VERSION 5.8 ;
BUSBITCHARS "[]" ;
DIVIDERCHAR "/" ;
UNITS
    DATABASE MICRONS 1000 ;
END UNITS

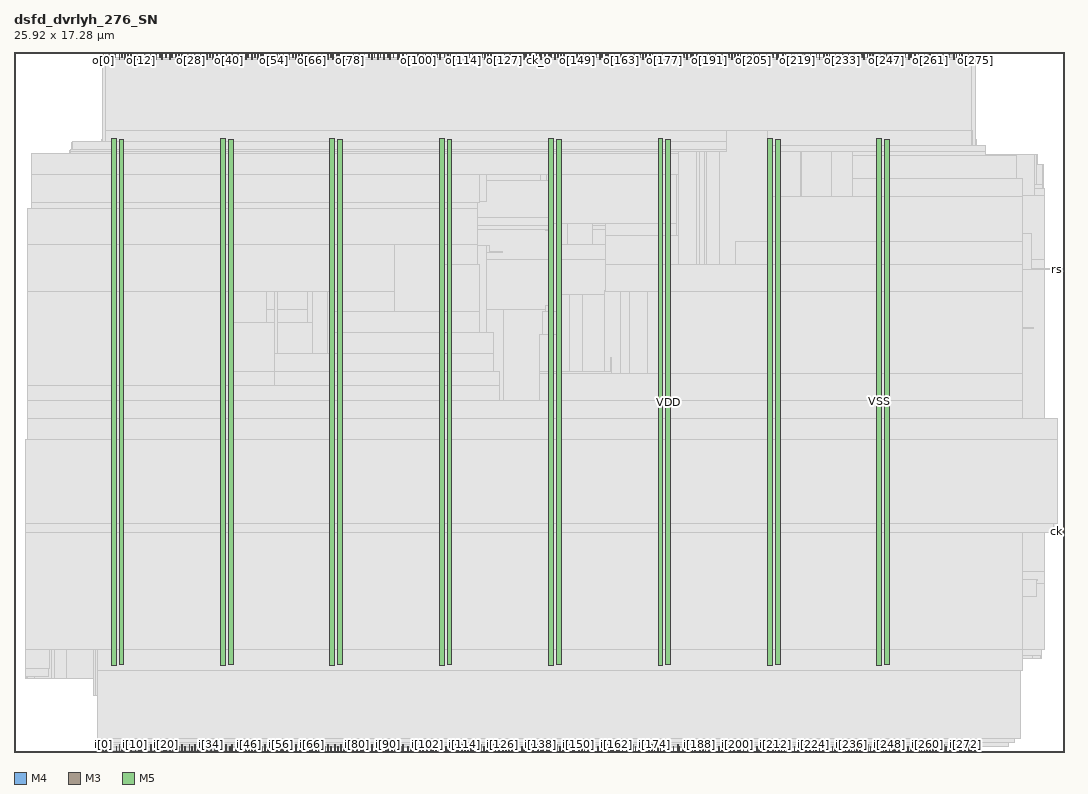
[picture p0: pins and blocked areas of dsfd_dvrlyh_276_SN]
MACRO dsfd_dvrlyh_276_SN
  FOREIGN dsfd_dvrlyh_276_SN 0 0 ;
  CLASS BLOCK ;
  SIZE 25.92 BY 17.28 ;
  PIN ck
    DIRECTION INPUT ;
    USE SIGNAL ;
    PORT
      LAYER M4 ;
        RECT  25.728 5.424 25.92 5.448 ;
    END
  END ck
  PIN ck_o
    DIRECTION OUTPUT ;
    USE SIGNAL ;
    PORT
      LAYER M3 ;
        RECT  12.96 17.136 12.978 17.28 ;
    END
  END ck_o
  PIN i[0]
    DIRECTION INPUT ;
    USE SIGNAL ;
    PORT
      LAYER M3 ;
        RECT  2.196 0 2.214 0.144 ;
    END
  END i[0]
  PIN i[100]
    DIRECTION INPUT ;
    USE SIGNAL ;
    PORT
      LAYER M3 ;
        RECT  10.008 0 10.026 0.144 ;
    END
  END i[100]
  PIN i[101]
    DIRECTION INPUT ;
    USE SIGNAL ;
    PORT
      LAYER M5 ;
        RECT  10.08 0 10.104 0.192 ;
    END
  END i[101]
  PIN i[102]
    DIRECTION INPUT ;
    USE SIGNAL ;
    PORT
      LAYER M3 ;
        RECT  10.188 0 10.206 0.144 ;
    END
  END i[102]
  PIN i[103]
    DIRECTION INPUT ;
    USE SIGNAL ;
    PORT
      LAYER M5 ;
        RECT  10.272 0 10.296 0.192 ;
    END
  END i[103]
  PIN i[104]
    DIRECTION INPUT ;
    USE SIGNAL ;
    PORT
      LAYER M3 ;
        RECT  10.332 0 10.35 0.144 ;
    END
  END i[104]
  PIN i[105]
    DIRECTION INPUT ;
    USE SIGNAL ;
    PORT
      LAYER M5 ;
        RECT  10.416 0 10.44 0.192 ;
    END
  END i[105]
  PIN i[106]
    DIRECTION INPUT ;
    USE SIGNAL ;
    PORT
      LAYER M3 ;
        RECT  10.476 0 10.494 0.144 ;
    END
  END i[106]
  PIN i[107]
    DIRECTION INPUT ;
    USE SIGNAL ;
    PORT
      LAYER M5 ;
        RECT  10.56 0 10.584 0.192 ;
    END
  END i[107]
  PIN i[108]
    DIRECTION INPUT ;
    USE SIGNAL ;
    PORT
      LAYER M3 ;
        RECT  10.656 0 10.674 0.144 ;
    END
  END i[108]
  PIN i[109]
    DIRECTION INPUT ;
    USE SIGNAL ;
    PORT
      LAYER M5 ;
        RECT  10.704 0 10.728 0.192 ;
    END
  END i[109]
  PIN i[10]
    DIRECTION INPUT ;
    USE SIGNAL ;
    PORT
      LAYER M3 ;
        RECT  2.988 0 3.006 0.144 ;
    END
  END i[10]
  PIN i[110]
    DIRECTION INPUT ;
    USE SIGNAL ;
    PORT
      LAYER M3 ;
        RECT  10.8 0 10.818 0.144 ;
    END
  END i[110]
  PIN i[111]
    DIRECTION INPUT ;
    USE SIGNAL ;
    PORT
      LAYER M5 ;
        RECT  10.896 0 10.92 0.192 ;
    END
  END i[111]
  PIN i[112]
    DIRECTION INPUT ;
    USE SIGNAL ;
    PORT
      LAYER M3 ;
        RECT  10.944 0 10.962 0.144 ;
    END
  END i[112]
  PIN i[113]
    DIRECTION INPUT ;
    USE SIGNAL ;
    PORT
      LAYER M5 ;
        RECT  11.04 0 11.064 0.192 ;
    END
  END i[113]
  PIN i[114]
    DIRECTION INPUT ;
    USE SIGNAL ;
    PORT
      LAYER M3 ;
        RECT  11.124 0 11.142 0.144 ;
    END
  END i[114]
  PIN i[115]
    DIRECTION INPUT ;
    USE SIGNAL ;
    PORT
      LAYER M5 ;
        RECT  11.184 0 11.208 0.192 ;
    END
  END i[115]
  PIN i[116]
    DIRECTION INPUT ;
    USE SIGNAL ;
    PORT
      LAYER M3 ;
        RECT  11.268 0 11.286 0.144 ;
    END
  END i[116]
  PIN i[117]
    DIRECTION INPUT ;
    USE SIGNAL ;
    PORT
      LAYER M5 ;
        RECT  11.328 0 11.352 0.192 ;
    END
  END i[117]
  PIN i[118]
    DIRECTION INPUT ;
    USE SIGNAL ;
    PORT
      LAYER M3 ;
        RECT  11.412 0 11.43 0.144 ;
    END
  END i[118]
  PIN i[119]
    DIRECTION INPUT ;
    USE SIGNAL ;
    PORT
      LAYER M5 ;
        RECT  11.52 0 11.544 0.192 ;
    END
  END i[119]
  PIN i[11]
    DIRECTION INPUT ;
    USE SIGNAL ;
    PORT
      LAYER M5 ;
        RECT  3.072 0 3.096 0.192 ;
    END
  END i[11]
  PIN i[120]
    DIRECTION INPUT ;
    USE SIGNAL ;
    PORT
      LAYER M3 ;
        RECT  11.592 0 11.61 0.144 ;
    END
  END i[120]
  PIN i[121]
    DIRECTION INPUT ;
    USE SIGNAL ;
    PORT
      LAYER M5 ;
        RECT  11.664 0 11.688 0.192 ;
    END
  END i[121]
  PIN i[122]
    DIRECTION INPUT ;
    USE SIGNAL ;
    PORT
      LAYER M3 ;
        RECT  11.736 0 11.754 0.144 ;
    END
  END i[122]
  PIN i[123]
    DIRECTION INPUT ;
    USE SIGNAL ;
    PORT
      LAYER M5 ;
        RECT  11.808 0 11.832 0.192 ;
    END
  END i[123]
  PIN i[124]
    DIRECTION INPUT ;
    USE SIGNAL ;
    PORT
      LAYER M3 ;
        RECT  11.88 0 11.898 0.144 ;
    END
  END i[124]
  PIN i[125]
    DIRECTION INPUT ;
    USE SIGNAL ;
    PORT
      LAYER M5 ;
        RECT  11.952 0 11.976 0.192 ;
    END
  END i[125]
  PIN i[126]
    DIRECTION INPUT ;
    USE SIGNAL ;
    PORT
      LAYER M3 ;
        RECT  12.06 0 12.078 0.144 ;
    END
  END i[126]
  PIN i[127]
    DIRECTION INPUT ;
    USE SIGNAL ;
    PORT
      LAYER M5 ;
        RECT  12.144 0 12.168 0.192 ;
    END
  END i[127]
  PIN i[128]
    DIRECTION INPUT ;
    USE SIGNAL ;
    PORT
      LAYER M3 ;
        RECT  12.204 0 12.222 0.144 ;
    END
  END i[128]
  PIN i[129]
    DIRECTION INPUT ;
    USE SIGNAL ;
    PORT
      LAYER M5 ;
        RECT  12.288 0 12.312 0.192 ;
    END
  END i[129]
  PIN i[12]
    DIRECTION INPUT ;
    USE SIGNAL ;
    PORT
      LAYER M3 ;
        RECT  3.132 0 3.15 0.144 ;
    END
  END i[12]
  PIN i[130]
    DIRECTION INPUT ;
    USE SIGNAL ;
    PORT
      LAYER M3 ;
        RECT  12.348 0 12.366 0.144 ;
    END
  END i[130]
  PIN i[131]
    DIRECTION INPUT ;
    USE SIGNAL ;
    PORT
      LAYER M5 ;
        RECT  12.432 0 12.456 0.192 ;
    END
  END i[131]
  PIN i[132]
    DIRECTION INPUT ;
    USE SIGNAL ;
    PORT
      LAYER M3 ;
        RECT  12.528 0 12.546 0.144 ;
    END
  END i[132]
  PIN i[133]
    DIRECTION INPUT ;
    USE SIGNAL ;
    PORT
      LAYER M5 ;
        RECT  12.576 0 12.6 0.192 ;
    END
  END i[133]
  PIN i[134]
    DIRECTION INPUT ;
    USE SIGNAL ;
    PORT
      LAYER M3 ;
        RECT  12.672 0 12.69 0.144 ;
    END
  END i[134]
  PIN i[135]
    DIRECTION INPUT ;
    USE SIGNAL ;
    PORT
      LAYER M5 ;
        RECT  12.768 0 12.792 0.192 ;
    END
  END i[135]
  PIN i[136]
    DIRECTION INPUT ;
    USE SIGNAL ;
    PORT
      LAYER M3 ;
        RECT  12.816 0 12.834 0.144 ;
    END
  END i[136]
  PIN i[137]
    DIRECTION INPUT ;
    USE SIGNAL ;
    PORT
      LAYER M5 ;
        RECT  12.912 0 12.936 0.192 ;
    END
  END i[137]
  PIN i[138]
    DIRECTION INPUT ;
    USE SIGNAL ;
    PORT
      LAYER M3 ;
        RECT  12.996 0 13.014 0.144 ;
    END
  END i[138]
  PIN i[139]
    DIRECTION INPUT ;
    USE SIGNAL ;
    PORT
      LAYER M5 ;
        RECT  13.056 0 13.08 0.192 ;
    END
  END i[139]
  PIN i[13]
    DIRECTION INPUT ;
    USE SIGNAL ;
    PORT
      LAYER M5 ;
        RECT  3.216 0 3.24 0.192 ;
    END
  END i[13]
  PIN i[140]
    DIRECTION INPUT ;
    USE SIGNAL ;
    PORT
      LAYER M3 ;
        RECT  13.14 0 13.158 0.144 ;
    END
  END i[140]
  PIN i[141]
    DIRECTION INPUT ;
    USE SIGNAL ;
    PORT
      LAYER M5 ;
        RECT  13.2 0 13.224 0.192 ;
    END
  END i[141]
  PIN i[142]
    DIRECTION INPUT ;
    USE SIGNAL ;
    PORT
      LAYER M3 ;
        RECT  13.32 0 13.338 0.144 ;
    END
  END i[142]
  PIN i[143]
    DIRECTION INPUT ;
    USE SIGNAL ;
    PORT
      LAYER M5 ;
        RECT  13.392 0 13.416 0.192 ;
    END
  END i[143]
  PIN i[144]
    DIRECTION INPUT ;
    USE SIGNAL ;
    PORT
      LAYER M3 ;
        RECT  13.464 0 13.482 0.144 ;
    END
  END i[144]
  PIN i[145]
    DIRECTION INPUT ;
    USE SIGNAL ;
    PORT
      LAYER M5 ;
        RECT  13.536 0 13.56 0.192 ;
    END
  END i[145]
  PIN i[146]
    DIRECTION INPUT ;
    USE SIGNAL ;
    PORT
      LAYER M3 ;
        RECT  13.608 0 13.626 0.144 ;
    END
  END i[146]
  PIN i[147]
    DIRECTION INPUT ;
    USE SIGNAL ;
    PORT
      LAYER M5 ;
        RECT  13.68 0 13.704 0.192 ;
    END
  END i[147]
  PIN i[148]
    DIRECTION INPUT ;
    USE SIGNAL ;
    PORT
      LAYER M3 ;
        RECT  13.788 0 13.806 0.144 ;
    END
  END i[148]
  PIN i[149]
    DIRECTION INPUT ;
    USE SIGNAL ;
    PORT
      LAYER M5 ;
        RECT  13.824 0 13.848 0.192 ;
    END
  END i[149]
  PIN i[14]
    DIRECTION INPUT ;
    USE SIGNAL ;
    PORT
      LAYER M3 ;
        RECT  3.276 0 3.294 0.144 ;
    END
  END i[14]
  PIN i[150]
    DIRECTION INPUT ;
    USE SIGNAL ;
    PORT
      LAYER M3 ;
        RECT  13.932 0 13.95 0.144 ;
    END
  END i[150]
  PIN i[151]
    DIRECTION INPUT ;
    USE SIGNAL ;
    PORT
      LAYER M5 ;
        RECT  14.016 0 14.04 0.192 ;
    END
  END i[151]
  PIN i[152]
    DIRECTION INPUT ;
    USE SIGNAL ;
    PORT
      LAYER M3 ;
        RECT  14.076 0 14.094 0.144 ;
    END
  END i[152]
  PIN i[153]
    DIRECTION INPUT ;
    USE SIGNAL ;
    PORT
      LAYER M5 ;
        RECT  14.16 0 14.184 0.192 ;
    END
  END i[153]
  PIN i[154]
    DIRECTION INPUT ;
    USE SIGNAL ;
    PORT
      LAYER M3 ;
        RECT  14.256 0 14.274 0.144 ;
    END
  END i[154]
  PIN i[155]
    DIRECTION INPUT ;
    USE SIGNAL ;
    PORT
      LAYER M5 ;
        RECT  14.304 0 14.328 0.192 ;
    END
  END i[155]
  PIN i[156]
    DIRECTION INPUT ;
    USE SIGNAL ;
    PORT
      LAYER M3 ;
        RECT  14.4 0 14.418 0.144 ;
    END
  END i[156]
  PIN i[157]
    DIRECTION INPUT ;
    USE SIGNAL ;
    PORT
      LAYER M5 ;
        RECT  14.496 0 14.52 0.192 ;
    END
  END i[157]
  PIN i[158]
    DIRECTION INPUT ;
    USE SIGNAL ;
    PORT
      LAYER M3 ;
        RECT  14.544 0 14.562 0.144 ;
    END
  END i[158]
  PIN i[159]
    DIRECTION INPUT ;
    USE SIGNAL ;
    PORT
      LAYER M5 ;
        RECT  14.64 0 14.664 0.192 ;
    END
  END i[159]
  PIN i[15]
    DIRECTION INPUT ;
    USE SIGNAL ;
    PORT
      LAYER M5 ;
        RECT  3.36 0 3.384 0.192 ;
    END
  END i[15]
  PIN i[160]
    DIRECTION INPUT ;
    USE SIGNAL ;
    PORT
      LAYER M3 ;
        RECT  14.724 0 14.742 0.144 ;
    END
  END i[160]
  PIN i[161]
    DIRECTION INPUT ;
    USE SIGNAL ;
    PORT
      LAYER M5 ;
        RECT  14.784 0 14.808 0.192 ;
    END
  END i[161]
  PIN i[162]
    DIRECTION INPUT ;
    USE SIGNAL ;
    PORT
      LAYER M3 ;
        RECT  14.868 0 14.886 0.144 ;
    END
  END i[162]
  PIN i[163]
    DIRECTION INPUT ;
    USE SIGNAL ;
    PORT
      LAYER M5 ;
        RECT  14.928 0 14.952 0.192 ;
    END
  END i[163]
  PIN i[164]
    DIRECTION INPUT ;
    USE SIGNAL ;
    PORT
      LAYER M3 ;
        RECT  15.012 0 15.03 0.144 ;
    END
  END i[164]
  PIN i[165]
    DIRECTION INPUT ;
    USE SIGNAL ;
    PORT
      LAYER M5 ;
        RECT  15.12 0 15.144 0.192 ;
    END
  END i[165]
  PIN i[166]
    DIRECTION INPUT ;
    USE SIGNAL ;
    PORT
      LAYER M3 ;
        RECT  15.192 0 15.21 0.144 ;
    END
  END i[166]
  PIN i[167]
    DIRECTION INPUT ;
    USE SIGNAL ;
    PORT
      LAYER M5 ;
        RECT  15.264 0 15.288 0.192 ;
    END
  END i[167]
  PIN i[168]
    DIRECTION INPUT ;
    USE SIGNAL ;
    PORT
      LAYER M3 ;
        RECT  15.336 0 15.354 0.144 ;
    END
  END i[168]
  PIN i[169]
    DIRECTION INPUT ;
    USE SIGNAL ;
    PORT
      LAYER M5 ;
        RECT  15.408 0 15.432 0.192 ;
    END
  END i[169]
  PIN i[16]
    DIRECTION INPUT ;
    USE SIGNAL ;
    PORT
      LAYER M3 ;
        RECT  3.456 0 3.474 0.144 ;
    END
  END i[16]
  PIN i[170]
    DIRECTION INPUT ;
    USE SIGNAL ;
    PORT
      LAYER M3 ;
        RECT  15.48 0 15.498 0.144 ;
    END
  END i[170]
  PIN i[171]
    DIRECTION INPUT ;
    USE SIGNAL ;
    PORT
      LAYER M5 ;
        RECT  15.552 0 15.576 0.192 ;
    END
  END i[171]
  PIN i[172]
    DIRECTION INPUT ;
    USE SIGNAL ;
    PORT
      LAYER M3 ;
        RECT  15.66 0 15.678 0.144 ;
    END
  END i[172]
  PIN i[173]
    DIRECTION INPUT ;
    USE SIGNAL ;
    PORT
      LAYER M5 ;
        RECT  15.744 0 15.768 0.192 ;
    END
  END i[173]
  PIN i[174]
    DIRECTION INPUT ;
    USE SIGNAL ;
    PORT
      LAYER M3 ;
        RECT  15.804 0 15.822 0.144 ;
    END
  END i[174]
  PIN i[175]
    DIRECTION INPUT ;
    USE SIGNAL ;
    PORT
      LAYER M5 ;
        RECT  15.888 0 15.912 0.192 ;
    END
  END i[175]
  PIN i[176]
    DIRECTION INPUT ;
    USE SIGNAL ;
    PORT
      LAYER M3 ;
        RECT  15.948 0 15.966 0.144 ;
    END
  END i[176]
  PIN i[177]
    DIRECTION INPUT ;
    USE SIGNAL ;
    PORT
      LAYER M5 ;
        RECT  16.032 0 16.056 0.192 ;
    END
  END i[177]
  PIN i[178]
    DIRECTION INPUT ;
    USE SIGNAL ;
    PORT
      LAYER M3 ;
        RECT  16.128 0 16.146 0.144 ;
    END
  END i[178]
  PIN i[179]
    DIRECTION INPUT ;
    USE SIGNAL ;
    PORT
      LAYER M5 ;
        RECT  16.176 0 16.2 0.192 ;
    END
  END i[179]
  PIN i[17]
    DIRECTION INPUT ;
    USE SIGNAL ;
    PORT
      LAYER M5 ;
        RECT  3.504 0 3.528 0.192 ;
    END
  END i[17]
  PIN i[180]
    DIRECTION INPUT ;
    USE SIGNAL ;
    PORT
      LAYER M3 ;
        RECT  16.272 0 16.29 0.144 ;
    END
  END i[180]
  PIN i[181]
    DIRECTION INPUT ;
    USE SIGNAL ;
    PORT
      LAYER M5 ;
        RECT  16.368 0 16.392 0.192 ;
    END
  END i[181]
  PIN i[182]
    DIRECTION INPUT ;
    USE SIGNAL ;
    PORT
      LAYER M3 ;
        RECT  16.416 0 16.434 0.144 ;
    END
  END i[182]
  PIN i[183]
    DIRECTION INPUT ;
    USE SIGNAL ;
    PORT
      LAYER M5 ;
        RECT  16.512 0 16.536 0.192 ;
    END
  END i[183]
  PIN i[184]
    DIRECTION INPUT ;
    USE SIGNAL ;
    PORT
      LAYER M3 ;
        RECT  16.596 0 16.614 0.144 ;
    END
  END i[184]
  PIN i[185]
    DIRECTION INPUT ;
    USE SIGNAL ;
    PORT
      LAYER M5 ;
        RECT  16.656 0 16.68 0.192 ;
    END
  END i[185]
  PIN i[186]
    DIRECTION INPUT ;
    USE SIGNAL ;
    PORT
      LAYER M3 ;
        RECT  16.74 0 16.758 0.144 ;
    END
  END i[186]
  PIN i[187]
    DIRECTION INPUT ;
    USE SIGNAL ;
    PORT
      LAYER M5 ;
        RECT  16.8 0 16.824 0.192 ;
    END
  END i[187]
  PIN i[188]
    DIRECTION INPUT ;
    USE SIGNAL ;
    PORT
      LAYER M3 ;
        RECT  16.92 0 16.938 0.144 ;
    END
  END i[188]
  PIN i[189]
    DIRECTION INPUT ;
    USE SIGNAL ;
    PORT
      LAYER M5 ;
        RECT  16.992 0 17.016 0.192 ;
    END
  END i[189]
  PIN i[18]
    DIRECTION INPUT ;
    USE SIGNAL ;
    PORT
      LAYER M3 ;
        RECT  3.6 0 3.618 0.144 ;
    END
  END i[18]
  PIN i[190]
    DIRECTION INPUT ;
    USE SIGNAL ;
    PORT
      LAYER M3 ;
        RECT  17.064 0 17.082 0.144 ;
    END
  END i[190]
  PIN i[191]
    DIRECTION INPUT ;
    USE SIGNAL ;
    PORT
      LAYER M5 ;
        RECT  17.136 0 17.16 0.192 ;
    END
  END i[191]
  PIN i[192]
    DIRECTION INPUT ;
    USE SIGNAL ;
    PORT
      LAYER M3 ;
        RECT  17.208 0 17.226 0.144 ;
    END
  END i[192]
  PIN i[193]
    DIRECTION INPUT ;
    USE SIGNAL ;
    PORT
      LAYER M5 ;
        RECT  17.28 0 17.304 0.192 ;
    END
  END i[193]
  PIN i[194]
    DIRECTION INPUT ;
    USE SIGNAL ;
    PORT
      LAYER M3 ;
        RECT  17.388 0 17.406 0.144 ;
    END
  END i[194]
  PIN i[195]
    DIRECTION INPUT ;
    USE SIGNAL ;
    PORT
      LAYER M5 ;
        RECT  17.472 0 17.496 0.192 ;
    END
  END i[195]
  PIN i[196]
    DIRECTION INPUT ;
    USE SIGNAL ;
    PORT
      LAYER M3 ;
        RECT  17.532 0 17.55 0.144 ;
    END
  END i[196]
  PIN i[197]
    DIRECTION INPUT ;
    USE SIGNAL ;
    PORT
      LAYER M5 ;
        RECT  17.616 0 17.64 0.192 ;
    END
  END i[197]
  PIN i[198]
    DIRECTION INPUT ;
    USE SIGNAL ;
    PORT
      LAYER M3 ;
        RECT  17.676 0 17.694 0.144 ;
    END
  END i[198]
  PIN i[199]
    DIRECTION INPUT ;
    USE SIGNAL ;
    PORT
      LAYER M5 ;
        RECT  17.76 0 17.784 0.192 ;
    END
  END i[199]
  PIN i[19]
    DIRECTION INPUT ;
    USE SIGNAL ;
    PORT
      LAYER M5 ;
        RECT  3.696 0 3.72 0.192 ;
    END
  END i[19]
  PIN i[1]
    DIRECTION INPUT ;
    USE SIGNAL ;
    PORT
      LAYER M5 ;
        RECT  2.256 0 2.28 0.192 ;
    END
  END i[1]
  PIN i[200]
    DIRECTION INPUT ;
    USE SIGNAL ;
    PORT
      LAYER M3 ;
        RECT  17.856 0 17.874 0.144 ;
    END
  END i[200]
  PIN i[201]
    DIRECTION INPUT ;
    USE SIGNAL ;
    PORT
      LAYER M5 ;
        RECT  17.904 0 17.928 0.192 ;
    END
  END i[201]
  PIN i[202]
    DIRECTION INPUT ;
    USE SIGNAL ;
    PORT
      LAYER M3 ;
        RECT  18 0 18.018 0.144 ;
    END
  END i[202]
  PIN i[203]
    DIRECTION INPUT ;
    USE SIGNAL ;
    PORT
      LAYER M5 ;
        RECT  18.096 0 18.12 0.192 ;
    END
  END i[203]
  PIN i[204]
    DIRECTION INPUT ;
    USE SIGNAL ;
    PORT
      LAYER M3 ;
        RECT  18.144 0 18.162 0.144 ;
    END
  END i[204]
  PIN i[205]
    DIRECTION INPUT ;
    USE SIGNAL ;
    PORT
      LAYER M5 ;
        RECT  18.24 0 18.264 0.192 ;
    END
  END i[205]
  PIN i[206]
    DIRECTION INPUT ;
    USE SIGNAL ;
    PORT
      LAYER M3 ;
        RECT  18.324 0 18.342 0.144 ;
    END
  END i[206]
  PIN i[207]
    DIRECTION INPUT ;
    USE SIGNAL ;
    PORT
      LAYER M5 ;
        RECT  18.384 0 18.408 0.192 ;
    END
  END i[207]
  PIN i[208]
    DIRECTION INPUT ;
    USE SIGNAL ;
    PORT
      LAYER M3 ;
        RECT  18.468 0 18.486 0.144 ;
    END
  END i[208]
  PIN i[209]
    DIRECTION INPUT ;
    USE SIGNAL ;
    PORT
      LAYER M5 ;
        RECT  18.528 0 18.552 0.192 ;
    END
  END i[209]
  PIN i[20]
    DIRECTION INPUT ;
    USE SIGNAL ;
    PORT
      LAYER M3 ;
        RECT  3.744 0 3.762 0.144 ;
    END
  END i[20]
  PIN i[210]
    DIRECTION INPUT ;
    USE SIGNAL ;
    PORT
      LAYER M3 ;
        RECT  18.612 0 18.63 0.144 ;
    END
  END i[210]
  PIN i[211]
    DIRECTION INPUT ;
    USE SIGNAL ;
    PORT
      LAYER M5 ;
        RECT  18.72 0 18.744 0.192 ;
    END
  END i[211]
  PIN i[212]
    DIRECTION INPUT ;
    USE SIGNAL ;
    PORT
      LAYER M3 ;
        RECT  18.792 0 18.81 0.144 ;
    END
  END i[212]
  PIN i[213]
    DIRECTION INPUT ;
    USE SIGNAL ;
    PORT
      LAYER M5 ;
        RECT  18.864 0 18.888 0.192 ;
    END
  END i[213]
  PIN i[214]
    DIRECTION INPUT ;
    USE SIGNAL ;
    PORT
      LAYER M3 ;
        RECT  18.936 0 18.954 0.144 ;
    END
  END i[214]
  PIN i[215]
    DIRECTION INPUT ;
    USE SIGNAL ;
    PORT
      LAYER M5 ;
        RECT  19.008 0 19.032 0.192 ;
    END
  END i[215]
  PIN i[216]
    DIRECTION INPUT ;
    USE SIGNAL ;
    PORT
      LAYER M3 ;
        RECT  19.08 0 19.098 0.144 ;
    END
  END i[216]
  PIN i[217]
    DIRECTION INPUT ;
    USE SIGNAL ;
    PORT
      LAYER M5 ;
        RECT  19.152 0 19.176 0.192 ;
    END
  END i[217]
  PIN i[218]
    DIRECTION INPUT ;
    USE SIGNAL ;
    PORT
      LAYER M3 ;
        RECT  19.26 0 19.278 0.144 ;
    END
  END i[218]
  PIN i[219]
    DIRECTION INPUT ;
    USE SIGNAL ;
    PORT
      LAYER M5 ;
        RECT  19.344 0 19.368 0.192 ;
    END
  END i[219]
  PIN i[21]
    DIRECTION INPUT ;
    USE SIGNAL ;
    PORT
      LAYER M5 ;
        RECT  3.84 0 3.864 0.192 ;
    END
  END i[21]
  PIN i[220]
    DIRECTION INPUT ;
    USE SIGNAL ;
    PORT
      LAYER M3 ;
        RECT  19.404 0 19.422 0.144 ;
    END
  END i[220]
  PIN i[221]
    DIRECTION INPUT ;
    USE SIGNAL ;
    PORT
      LAYER M5 ;
        RECT  19.488 0 19.512 0.192 ;
    END
  END i[221]
  PIN i[222]
    DIRECTION INPUT ;
    USE SIGNAL ;
    PORT
      LAYER M3 ;
        RECT  19.548 0 19.566 0.144 ;
    END
  END i[222]
  PIN i[223]
    DIRECTION INPUT ;
    USE SIGNAL ;
    PORT
      LAYER M5 ;
        RECT  19.632 0 19.656 0.192 ;
    END
  END i[223]
  PIN i[224]
    DIRECTION INPUT ;
    USE SIGNAL ;
    PORT
      LAYER M3 ;
        RECT  19.728 0 19.746 0.144 ;
    END
  END i[224]
  PIN i[225]
    DIRECTION INPUT ;
    USE SIGNAL ;
    PORT
      LAYER M5 ;
        RECT  19.776 0 19.8 0.192 ;
    END
  END i[225]
  PIN i[226]
    DIRECTION INPUT ;
    USE SIGNAL ;
    PORT
      LAYER M3 ;
        RECT  19.872 0 19.89 0.144 ;
    END
  END i[226]
  PIN i[227]
    DIRECTION INPUT ;
    USE SIGNAL ;
    PORT
      LAYER M5 ;
        RECT  19.968 0 19.992 0.192 ;
    END
  END i[227]
  PIN i[228]
    DIRECTION INPUT ;
    USE SIGNAL ;
    PORT
      LAYER M3 ;
        RECT  20.016 0 20.034 0.144 ;
    END
  END i[228]
  PIN i[229]
    DIRECTION INPUT ;
    USE SIGNAL ;
    PORT
      LAYER M5 ;
        RECT  20.112 0 20.136 0.192 ;
    END
  END i[229]
  PIN i[22]
    DIRECTION INPUT ;
    USE SIGNAL ;
    PORT
      LAYER M3 ;
        RECT  3.924 0 3.942 0.144 ;
    END
  END i[22]
  PIN i[230]
    DIRECTION INPUT ;
    USE SIGNAL ;
    PORT
      LAYER M3 ;
        RECT  20.196 0 20.214 0.144 ;
    END
  END i[230]
  PIN i[231]
    DIRECTION INPUT ;
    USE SIGNAL ;
    PORT
      LAYER M5 ;
        RECT  20.256 0 20.28 0.192 ;
    END
  END i[231]
  PIN i[232]
    DIRECTION INPUT ;
    USE SIGNAL ;
    PORT
      LAYER M3 ;
        RECT  20.34 0 20.358 0.144 ;
    END
  END i[232]
  PIN i[233]
    DIRECTION INPUT ;
    USE SIGNAL ;
    PORT
      LAYER M5 ;
        RECT  20.4 0 20.424 0.192 ;
    END
  END i[233]
  PIN i[234]
    DIRECTION INPUT ;
    USE SIGNAL ;
    PORT
      LAYER M3 ;
        RECT  20.52 0 20.538 0.144 ;
    END
  END i[234]
  PIN i[235]
    DIRECTION INPUT ;
    USE SIGNAL ;
    PORT
      LAYER M5 ;
        RECT  20.592 0 20.616 0.192 ;
    END
  END i[235]
  PIN i[236]
    DIRECTION INPUT ;
    USE SIGNAL ;
    PORT
      LAYER M3 ;
        RECT  20.664 0 20.682 0.144 ;
    END
  END i[236]
  PIN i[237]
    DIRECTION INPUT ;
    USE SIGNAL ;
    PORT
      LAYER M5 ;
        RECT  20.736 0 20.76 0.192 ;
    END
  END i[237]
  PIN i[238]
    DIRECTION INPUT ;
    USE SIGNAL ;
    PORT
      LAYER M3 ;
        RECT  20.808 0 20.826 0.144 ;
    END
  END i[238]
  PIN i[239]
    DIRECTION INPUT ;
    USE SIGNAL ;
    PORT
      LAYER M5 ;
        RECT  20.88 0 20.904 0.192 ;
    END
  END i[239]
  PIN i[23]
    DIRECTION INPUT ;
    USE SIGNAL ;
    PORT
      LAYER M5 ;
        RECT  3.984 0 4.008 0.192 ;
    END
  END i[23]
  PIN i[240]
    DIRECTION INPUT ;
    USE SIGNAL ;
    PORT
      LAYER M3 ;
        RECT  20.988 0 21.006 0.144 ;
    END
  END i[240]
  PIN i[241]
    DIRECTION INPUT ;
    USE SIGNAL ;
    PORT
      LAYER M5 ;
        RECT  21.072 0 21.096 0.192 ;
    END
  END i[241]
  PIN i[242]
    DIRECTION INPUT ;
    USE SIGNAL ;
    PORT
      LAYER M3 ;
        RECT  21.132 0 21.15 0.144 ;
    END
  END i[242]
  PIN i[243]
    DIRECTION INPUT ;
    USE SIGNAL ;
    PORT
      LAYER M5 ;
        RECT  21.216 0 21.24 0.192 ;
    END
  END i[243]
  PIN i[244]
    DIRECTION INPUT ;
    USE SIGNAL ;
    PORT
      LAYER M3 ;
        RECT  21.276 0 21.294 0.144 ;
    END
  END i[244]
  PIN i[245]
    DIRECTION INPUT ;
    USE SIGNAL ;
    PORT
      LAYER M5 ;
        RECT  21.36 0 21.384 0.192 ;
    END
  END i[245]
  PIN i[246]
    DIRECTION INPUT ;
    USE SIGNAL ;
    PORT
      LAYER M3 ;
        RECT  21.456 0 21.474 0.144 ;
    END
  END i[246]
  PIN i[247]
    DIRECTION INPUT ;
    USE SIGNAL ;
    PORT
      LAYER M5 ;
        RECT  21.504 0 21.528 0.192 ;
    END
  END i[247]
  PIN i[248]
    DIRECTION INPUT ;
    USE SIGNAL ;
    PORT
      LAYER M3 ;
        RECT  21.6 0 21.618 0.144 ;
    END
  END i[248]
  PIN i[249]
    DIRECTION INPUT ;
    USE SIGNAL ;
    PORT
      LAYER M5 ;
        RECT  21.696 0 21.72 0.192 ;
    END
  END i[249]
  PIN i[24]
    DIRECTION INPUT ;
    USE SIGNAL ;
    PORT
      LAYER M3 ;
        RECT  4.068 0 4.086 0.144 ;
    END
  END i[24]
  PIN i[250]
    DIRECTION INPUT ;
    USE SIGNAL ;
    PORT
      LAYER M3 ;
        RECT  21.744 0 21.762 0.144 ;
    END
  END i[250]
  PIN i[251]
    DIRECTION INPUT ;
    USE SIGNAL ;
    PORT
      LAYER M5 ;
        RECT  21.84 0 21.864 0.192 ;
    END
  END i[251]
  PIN i[252]
    DIRECTION INPUT ;
    USE SIGNAL ;
    PORT
      LAYER M3 ;
        RECT  21.924 0 21.942 0.144 ;
    END
  END i[252]
  PIN i[253]
    DIRECTION INPUT ;
    USE SIGNAL ;
    PORT
      LAYER M5 ;
        RECT  21.984 0 22.008 0.192 ;
    END
  END i[253]
  PIN i[254]
    DIRECTION INPUT ;
    USE SIGNAL ;
    PORT
      LAYER M3 ;
        RECT  22.068 0 22.086 0.144 ;
    END
  END i[254]
  PIN i[255]
    DIRECTION INPUT ;
    USE SIGNAL ;
    PORT
      LAYER M5 ;
        RECT  22.128 0 22.152 0.192 ;
    END
  END i[255]
  PIN i[256]
    DIRECTION INPUT ;
    USE SIGNAL ;
    PORT
      LAYER M3 ;
        RECT  22.212 0 22.23 0.144 ;
    END
  END i[256]
  PIN i[257]
    DIRECTION INPUT ;
    USE SIGNAL ;
    PORT
      LAYER M5 ;
        RECT  22.32 0 22.344 0.192 ;
    END
  END i[257]
  PIN i[258]
    DIRECTION INPUT ;
    USE SIGNAL ;
    PORT
      LAYER M3 ;
        RECT  22.392 0 22.41 0.144 ;
    END
  END i[258]
  PIN i[259]
    DIRECTION INPUT ;
    USE SIGNAL ;
    PORT
      LAYER M5 ;
        RECT  22.464 0 22.488 0.192 ;
    END
  END i[259]
  PIN i[25]
    DIRECTION INPUT ;
    USE SIGNAL ;
    PORT
      LAYER M5 ;
        RECT  4.128 0 4.152 0.192 ;
    END
  END i[25]
  PIN i[260]
    DIRECTION INPUT ;
    USE SIGNAL ;
    PORT
      LAYER M3 ;
        RECT  22.536 0 22.554 0.144 ;
    END
  END i[260]
  PIN i[261]
    DIRECTION INPUT ;
    USE SIGNAL ;
    PORT
      LAYER M5 ;
        RECT  22.608 0 22.632 0.192 ;
    END
  END i[261]
  PIN i[262]
    DIRECTION INPUT ;
    USE SIGNAL ;
    PORT
      LAYER M3 ;
        RECT  22.68 0 22.698 0.144 ;
    END
  END i[262]
  PIN i[263]
    DIRECTION INPUT ;
    USE SIGNAL ;
    PORT
      LAYER M5 ;
        RECT  22.752 0 22.776 0.192 ;
    END
  END i[263]
  PIN i[264]
    DIRECTION INPUT ;
    USE SIGNAL ;
    PORT
      LAYER M3 ;
        RECT  22.86 0 22.878 0.144 ;
    END
  END i[264]
  PIN i[265]
    DIRECTION INPUT ;
    USE SIGNAL ;
    PORT
      LAYER M5 ;
        RECT  22.944 0 22.968 0.192 ;
    END
  END i[265]
  PIN i[266]
    DIRECTION INPUT ;
    USE SIGNAL ;
    PORT
      LAYER M3 ;
        RECT  23.004 0 23.022 0.144 ;
    END
  END i[266]
  PIN i[267]
    DIRECTION INPUT ;
    USE SIGNAL ;
    PORT
      LAYER M5 ;
        RECT  23.088 0 23.112 0.192 ;
    END
  END i[267]
  PIN i[268]
    DIRECTION INPUT ;
    USE SIGNAL ;
    PORT
      LAYER M3 ;
        RECT  23.148 0 23.166 0.144 ;
    END
  END i[268]
  PIN i[269]
    DIRECTION INPUT ;
    USE SIGNAL ;
    PORT
      LAYER M5 ;
        RECT  23.232 0 23.256 0.192 ;
    END
  END i[269]
  PIN i[26]
    DIRECTION INPUT ;
    USE SIGNAL ;
    PORT
      LAYER M3 ;
        RECT  4.212 0 4.23 0.144 ;
    END
  END i[26]
  PIN i[270]
    DIRECTION INPUT ;
    USE SIGNAL ;
    PORT
      LAYER M3 ;
        RECT  23.328 0 23.346 0.144 ;
    END
  END i[270]
  PIN i[271]
    DIRECTION INPUT ;
    USE SIGNAL ;
    PORT
      LAYER M5 ;
        RECT  23.376 0 23.4 0.192 ;
    END
  END i[271]
  PIN i[272]
    DIRECTION INPUT ;
    USE SIGNAL ;
    PORT
      LAYER M3 ;
        RECT  23.472 0 23.49 0.144 ;
    END
  END i[272]
  PIN i[273]
    DIRECTION INPUT ;
    USE SIGNAL ;
    PORT
      LAYER M5 ;
        RECT  23.568 0 23.592 0.192 ;
    END
  END i[273]
  PIN i[274]
    DIRECTION INPUT ;
    USE SIGNAL ;
    PORT
      LAYER M3 ;
        RECT  23.616 0 23.634 0.144 ;
    END
  END i[274]
  PIN i[275]
    DIRECTION INPUT ;
    USE SIGNAL ;
    PORT
      LAYER M5 ;
        RECT  23.712 0 23.736 0.192 ;
    END
  END i[275]
  PIN i[27]
    DIRECTION INPUT ;
    USE SIGNAL ;
    PORT
      LAYER M5 ;
        RECT  4.32 0 4.344 0.192 ;
    END
  END i[27]
  PIN i[28]
    DIRECTION INPUT ;
    USE SIGNAL ;
    PORT
      LAYER M3 ;
        RECT  4.392 0 4.41 0.144 ;
    END
  END i[28]
  PIN i[29]
    DIRECTION INPUT ;
    USE SIGNAL ;
    PORT
      LAYER M5 ;
        RECT  4.464 0 4.488 0.192 ;
    END
  END i[29]
  PIN i[2]
    DIRECTION INPUT ;
    USE SIGNAL ;
    PORT
      LAYER M3 ;
        RECT  2.34 0 2.358 0.144 ;
    END
  END i[2]
  PIN i[30]
    DIRECTION INPUT ;
    USE SIGNAL ;
    PORT
      LAYER M3 ;
        RECT  4.536 0 4.554 0.144 ;
    END
  END i[30]
  PIN i[31]
    DIRECTION INPUT ;
    USE SIGNAL ;
    PORT
      LAYER M5 ;
        RECT  4.608 0 4.632 0.192 ;
    END
  END i[31]
  PIN i[32]
    DIRECTION INPUT ;
    USE SIGNAL ;
    PORT
      LAYER M3 ;
        RECT  4.68 0 4.698 0.144 ;
    END
  END i[32]
  PIN i[33]
    DIRECTION INPUT ;
    USE SIGNAL ;
    PORT
      LAYER M5 ;
        RECT  4.752 0 4.776 0.192 ;
    END
  END i[33]
  PIN i[34]
    DIRECTION INPUT ;
    USE SIGNAL ;
    PORT
      LAYER M3 ;
        RECT  4.86 0 4.878 0.144 ;
    END
  END i[34]
  PIN i[35]
    DIRECTION INPUT ;
    USE SIGNAL ;
    PORT
      LAYER M5 ;
        RECT  4.944 0 4.968 0.192 ;
    END
  END i[35]
  PIN i[36]
    DIRECTION INPUT ;
    USE SIGNAL ;
    PORT
      LAYER M3 ;
        RECT  5.004 0 5.022 0.144 ;
    END
  END i[36]
  PIN i[37]
    DIRECTION INPUT ;
    USE SIGNAL ;
    PORT
      LAYER M5 ;
        RECT  5.088 0 5.112 0.192 ;
    END
  END i[37]
  PIN i[38]
    DIRECTION INPUT ;
    USE SIGNAL ;
    PORT
      LAYER M3 ;
        RECT  5.148 0 5.166 0.144 ;
    END
  END i[38]
  PIN i[39]
    DIRECTION INPUT ;
    USE SIGNAL ;
    PORT
      LAYER M5 ;
        RECT  5.232 0 5.256 0.192 ;
    END
  END i[39]
  PIN i[3]
    DIRECTION INPUT ;
    USE SIGNAL ;
    PORT
      LAYER M5 ;
        RECT  2.4 0 2.424 0.192 ;
    END
  END i[3]
  PIN i[40]
    DIRECTION INPUT ;
    USE SIGNAL ;
    PORT
      LAYER M3 ;
        RECT  5.328 0 5.346 0.144 ;
    END
  END i[40]
  PIN i[41]
    DIRECTION INPUT ;
    USE SIGNAL ;
    PORT
      LAYER M5 ;
        RECT  5.376 0 5.4 0.192 ;
    END
  END i[41]
  PIN i[42]
    DIRECTION INPUT ;
    USE SIGNAL ;
    PORT
      LAYER M3 ;
        RECT  5.472 0 5.49 0.144 ;
    END
  END i[42]
  PIN i[43]
    DIRECTION INPUT ;
    USE SIGNAL ;
    PORT
      LAYER M5 ;
        RECT  5.568 0 5.592 0.192 ;
    END
  END i[43]
  PIN i[44]
    DIRECTION INPUT ;
    USE SIGNAL ;
    PORT
      LAYER M3 ;
        RECT  5.616 0 5.634 0.144 ;
    END
  END i[44]
  PIN i[45]
    DIRECTION INPUT ;
    USE SIGNAL ;
    PORT
      LAYER M5 ;
        RECT  5.712 0 5.736 0.192 ;
    END
  END i[45]
  PIN i[46]
    DIRECTION INPUT ;
    USE SIGNAL ;
    PORT
      LAYER M3 ;
        RECT  5.796 0 5.814 0.144 ;
    END
  END i[46]
  PIN i[47]
    DIRECTION INPUT ;
    USE SIGNAL ;
    PORT
      LAYER M5 ;
        RECT  5.856 0 5.88 0.192 ;
    END
  END i[47]
  PIN i[48]
    DIRECTION INPUT ;
    USE SIGNAL ;
    PORT
      LAYER M3 ;
        RECT  5.94 0 5.958 0.144 ;
    END
  END i[48]
  PIN i[49]
    DIRECTION INPUT ;
    USE SIGNAL ;
    PORT
      LAYER M5 ;
        RECT  6 0 6.024 0.192 ;
    END
  END i[49]
  PIN i[4]
    DIRECTION INPUT ;
    USE SIGNAL ;
    PORT
      LAYER M3 ;
        RECT  2.52 0 2.538 0.144 ;
    END
  END i[4]
  PIN i[50]
    DIRECTION INPUT ;
    USE SIGNAL ;
    PORT
      LAYER M3 ;
        RECT  6.12 0 6.138 0.144 ;
    END
  END i[50]
  PIN i[51]
    DIRECTION INPUT ;
    USE SIGNAL ;
    PORT
      LAYER M5 ;
        RECT  6.192 0 6.216 0.192 ;
    END
  END i[51]
  PIN i[52]
    DIRECTION INPUT ;
    USE SIGNAL ;
    PORT
      LAYER M3 ;
        RECT  6.264 0 6.282 0.144 ;
    END
  END i[52]
  PIN i[53]
    DIRECTION INPUT ;
    USE SIGNAL ;
    PORT
      LAYER M5 ;
        RECT  6.336 0 6.36 0.192 ;
    END
  END i[53]
  PIN i[54]
    DIRECTION INPUT ;
    USE SIGNAL ;
    PORT
      LAYER M3 ;
        RECT  6.408 0 6.426 0.144 ;
    END
  END i[54]
  PIN i[55]
    DIRECTION INPUT ;
    USE SIGNAL ;
    PORT
      LAYER M5 ;
        RECT  6.48 0 6.504 0.192 ;
    END
  END i[55]
  PIN i[56]
    DIRECTION INPUT ;
    USE SIGNAL ;
    PORT
      LAYER M3 ;
        RECT  6.588 0 6.606 0.144 ;
    END
  END i[56]
  PIN i[57]
    DIRECTION INPUT ;
    USE SIGNAL ;
    PORT
      LAYER M5 ;
        RECT  6.624 0 6.648 0.192 ;
    END
  END i[57]
  PIN i[58]
    DIRECTION INPUT ;
    USE SIGNAL ;
    PORT
      LAYER M3 ;
        RECT  6.732 0 6.75 0.144 ;
    END
  END i[58]
  PIN i[59]
    DIRECTION INPUT ;
    USE SIGNAL ;
    PORT
      LAYER M5 ;
        RECT  6.816 0 6.84 0.192 ;
    END
  END i[59]
  PIN i[5]
    DIRECTION INPUT ;
    USE SIGNAL ;
    PORT
      LAYER M5 ;
        RECT  2.592 0 2.616 0.192 ;
    END
  END i[5]
  PIN i[60]
    DIRECTION INPUT ;
    USE SIGNAL ;
    PORT
      LAYER M3 ;
        RECT  6.876 0 6.894 0.144 ;
    END
  END i[60]
  PIN i[61]
    DIRECTION INPUT ;
    USE SIGNAL ;
    PORT
      LAYER M5 ;
        RECT  6.96 0 6.984 0.192 ;
    END
  END i[61]
  PIN i[62]
    DIRECTION INPUT ;
    USE SIGNAL ;
    PORT
      LAYER M3 ;
        RECT  7.056 0 7.074 0.144 ;
    END
  END i[62]
  PIN i[63]
    DIRECTION INPUT ;
    USE SIGNAL ;
    PORT
      LAYER M5 ;
        RECT  7.104 0 7.128 0.192 ;
    END
  END i[63]
  PIN i[64]
    DIRECTION INPUT ;
    USE SIGNAL ;
    PORT
      LAYER M3 ;
        RECT  7.2 0 7.218 0.144 ;
    END
  END i[64]
  PIN i[65]
    DIRECTION INPUT ;
    USE SIGNAL ;
    PORT
      LAYER M5 ;
        RECT  7.296 0 7.32 0.192 ;
    END
  END i[65]
  PIN i[66]
    DIRECTION INPUT ;
    USE SIGNAL ;
    PORT
      LAYER M3 ;
        RECT  7.344 0 7.362 0.144 ;
    END
  END i[66]
  PIN i[67]
    DIRECTION INPUT ;
    USE SIGNAL ;
    PORT
      LAYER M5 ;
        RECT  7.44 0 7.464 0.192 ;
    END
  END i[67]
  PIN i[68]
    DIRECTION INPUT ;
    USE SIGNAL ;
    PORT
      LAYER M3 ;
        RECT  7.524 0 7.542 0.144 ;
    END
  END i[68]
  PIN i[69]
    DIRECTION INPUT ;
    USE SIGNAL ;
    PORT
      LAYER M5 ;
        RECT  7.584 0 7.608 0.192 ;
    END
  END i[69]
  PIN i[6]
    DIRECTION INPUT ;
    USE SIGNAL ;
    PORT
      LAYER M3 ;
        RECT  2.664 0 2.682 0.144 ;
    END
  END i[6]
  PIN i[70]
    DIRECTION INPUT ;
    USE SIGNAL ;
    PORT
      LAYER M3 ;
        RECT  7.668 0 7.686 0.144 ;
    END
  END i[70]
  PIN i[71]
    DIRECTION INPUT ;
    USE SIGNAL ;
    PORT
      LAYER M5 ;
        RECT  7.728 0 7.752 0.192 ;
    END
  END i[71]
  PIN i[72]
    DIRECTION INPUT ;
    USE SIGNAL ;
    PORT
      LAYER M3 ;
        RECT  7.812 0 7.83 0.144 ;
    END
  END i[72]
  PIN i[73]
    DIRECTION INPUT ;
    USE SIGNAL ;
    PORT
      LAYER M5 ;
        RECT  7.92 0 7.944 0.192 ;
    END
  END i[73]
  PIN i[74]
    DIRECTION INPUT ;
    USE SIGNAL ;
    PORT
      LAYER M3 ;
        RECT  7.992 0 8.01 0.144 ;
    END
  END i[74]
  PIN i[75]
    DIRECTION INPUT ;
    USE SIGNAL ;
    PORT
      LAYER M5 ;
        RECT  8.064 0 8.088 0.192 ;
    END
  END i[75]
  PIN i[76]
    DIRECTION INPUT ;
    USE SIGNAL ;
    PORT
      LAYER M3 ;
        RECT  8.136 0 8.154 0.144 ;
    END
  END i[76]
  PIN i[77]
    DIRECTION INPUT ;
    USE SIGNAL ;
    PORT
      LAYER M5 ;
        RECT  8.208 0 8.232 0.192 ;
    END
  END i[77]
  PIN i[78]
    DIRECTION INPUT ;
    USE SIGNAL ;
    PORT
      LAYER M3 ;
        RECT  8.28 0 8.298 0.144 ;
    END
  END i[78]
  PIN i[79]
    DIRECTION INPUT ;
    USE SIGNAL ;
    PORT
      LAYER M5 ;
        RECT  8.352 0 8.376 0.192 ;
    END
  END i[79]
  PIN i[7]
    DIRECTION INPUT ;
    USE SIGNAL ;
    PORT
      LAYER M5 ;
        RECT  2.736 0 2.76 0.192 ;
    END
  END i[7]
  PIN i[80]
    DIRECTION INPUT ;
    USE SIGNAL ;
    PORT
      LAYER M3 ;
        RECT  8.46 0 8.478 0.144 ;
    END
  END i[80]
  PIN i[81]
    DIRECTION INPUT ;
    USE SIGNAL ;
    PORT
      LAYER M5 ;
        RECT  8.544 0 8.568 0.192 ;
    END
  END i[81]
  PIN i[82]
    DIRECTION INPUT ;
    USE SIGNAL ;
    PORT
      LAYER M3 ;
        RECT  8.604 0 8.622 0.144 ;
    END
  END i[82]
  PIN i[83]
    DIRECTION INPUT ;
    USE SIGNAL ;
    PORT
      LAYER M5 ;
        RECT  8.688 0 8.712 0.192 ;
    END
  END i[83]
  PIN i[84]
    DIRECTION INPUT ;
    USE SIGNAL ;
    PORT
      LAYER M3 ;
        RECT  8.748 0 8.766 0.144 ;
    END
  END i[84]
  PIN i[85]
    DIRECTION INPUT ;
    USE SIGNAL ;
    PORT
      LAYER M5 ;
        RECT  8.832 0 8.856 0.192 ;
    END
  END i[85]
  PIN i[86]
    DIRECTION INPUT ;
    USE SIGNAL ;
    PORT
      LAYER M3 ;
        RECT  8.928 0 8.946 0.144 ;
    END
  END i[86]
  PIN i[87]
    DIRECTION INPUT ;
    USE SIGNAL ;
    PORT
      LAYER M5 ;
        RECT  8.976 0 9 0.192 ;
    END
  END i[87]
  PIN i[88]
    DIRECTION INPUT ;
    USE SIGNAL ;
    PORT
      LAYER M3 ;
        RECT  9.072 0 9.09 0.144 ;
    END
  END i[88]
  PIN i[89]
    DIRECTION INPUT ;
    USE SIGNAL ;
    PORT
      LAYER M5 ;
        RECT  9.168 0 9.192 0.192 ;
    END
  END i[89]
  PIN i[8]
    DIRECTION INPUT ;
    USE SIGNAL ;
    PORT
      LAYER M3 ;
        RECT  2.808 0 2.826 0.144 ;
    END
  END i[8]
  PIN i[90]
    DIRECTION INPUT ;
    USE SIGNAL ;
    PORT
      LAYER M3 ;
        RECT  9.216 0 9.234 0.144 ;
    END
  END i[90]
  PIN i[91]
    DIRECTION INPUT ;
    USE SIGNAL ;
    PORT
      LAYER M5 ;
        RECT  9.312 0 9.336 0.192 ;
    END
  END i[91]
  PIN i[92]
    DIRECTION INPUT ;
    USE SIGNAL ;
    PORT
      LAYER M3 ;
        RECT  9.396 0 9.414 0.144 ;
    END
  END i[92]
  PIN i[93]
    DIRECTION INPUT ;
    USE SIGNAL ;
    PORT
      LAYER M5 ;
        RECT  9.456 0 9.48 0.192 ;
    END
  END i[93]
  PIN i[94]
    DIRECTION INPUT ;
    USE SIGNAL ;
    PORT
      LAYER M3 ;
        RECT  9.54 0 9.558 0.144 ;
    END
  END i[94]
  PIN i[95]
    DIRECTION INPUT ;
    USE SIGNAL ;
    PORT
      LAYER M5 ;
        RECT  9.6 0 9.624 0.192 ;
    END
  END i[95]
  PIN i[96]
    DIRECTION INPUT ;
    USE SIGNAL ;
    PORT
      LAYER M3 ;
        RECT  9.72 0 9.738 0.144 ;
    END
  END i[96]
  PIN i[97]
    DIRECTION INPUT ;
    USE SIGNAL ;
    PORT
      LAYER M5 ;
        RECT  9.792 0 9.816 0.192 ;
    END
  END i[97]
  PIN i[98]
    DIRECTION INPUT ;
    USE SIGNAL ;
    PORT
      LAYER M3 ;
        RECT  9.864 0 9.882 0.144 ;
    END
  END i[98]
  PIN i[99]
    DIRECTION INPUT ;
    USE SIGNAL ;
    PORT
      LAYER M5 ;
        RECT  9.936 0 9.96 0.192 ;
    END
  END i[99]
  PIN i[9]
    DIRECTION INPUT ;
    USE SIGNAL ;
    PORT
      LAYER M5 ;
        RECT  2.88 0 2.904 0.192 ;
    END
  END i[9]
  PIN o[0]
    DIRECTION OUTPUT ;
    USE SIGNAL ;
    PORT
      LAYER M3 ;
        RECT  2.196 17.136 2.214 17.28 ;
    END
  END o[0]
  PIN o[100]
    DIRECTION OUTPUT ;
    USE SIGNAL ;
    PORT
      LAYER M3 ;
        RECT  9.972 17.136 9.99 17.28 ;
    END
  END o[100]
  PIN o[101]
    DIRECTION OUTPUT ;
    USE SIGNAL ;
    PORT
      LAYER M5 ;
        RECT  10.08 17.088 10.104 17.28 ;
    END
  END o[101]
  PIN o[102]
    DIRECTION OUTPUT ;
    USE SIGNAL ;
    PORT
      LAYER M3 ;
        RECT  10.152 17.136 10.17 17.28 ;
    END
  END o[102]
  PIN o[103]
    DIRECTION OUTPUT ;
    USE SIGNAL ;
    PORT
      LAYER M5 ;
        RECT  10.224 17.088 10.248 17.28 ;
    END
  END o[103]
  PIN o[104]
    DIRECTION OUTPUT ;
    USE SIGNAL ;
    PORT
      LAYER M3 ;
        RECT  10.296 17.136 10.314 17.28 ;
    END
  END o[104]
  PIN o[105]
    DIRECTION OUTPUT ;
    USE SIGNAL ;
    PORT
      LAYER M5 ;
        RECT  10.368 17.088 10.392 17.28 ;
    END
  END o[105]
  PIN o[106]
    DIRECTION OUTPUT ;
    USE SIGNAL ;
    PORT
      LAYER M3 ;
        RECT  10.44 17.136 10.458 17.28 ;
    END
  END o[106]
  PIN o[107]
    DIRECTION OUTPUT ;
    USE SIGNAL ;
    PORT
      LAYER M5 ;
        RECT  10.512 17.088 10.536 17.28 ;
    END
  END o[107]
  PIN o[108]
    DIRECTION OUTPUT ;
    USE SIGNAL ;
    PORT
      LAYER M3 ;
        RECT  10.62 17.136 10.638 17.28 ;
    END
  END o[108]
  PIN o[109]
    DIRECTION OUTPUT ;
    USE SIGNAL ;
    PORT
      LAYER M5 ;
        RECT  10.704 17.088 10.728 17.28 ;
    END
  END o[109]
  PIN o[10]
    DIRECTION OUTPUT ;
    USE SIGNAL ;
    PORT
      LAYER M3 ;
        RECT  2.952 17.136 2.97 17.28 ;
    END
  END o[10]
  PIN o[110]
    DIRECTION OUTPUT ;
    USE SIGNAL ;
    PORT
      LAYER M3 ;
        RECT  10.764 17.136 10.782 17.28 ;
    END
  END o[110]
  PIN o[111]
    DIRECTION OUTPUT ;
    USE SIGNAL ;
    PORT
      LAYER M5 ;
        RECT  10.848 17.088 10.872 17.28 ;
    END
  END o[111]
  PIN o[112]
    DIRECTION OUTPUT ;
    USE SIGNAL ;
    PORT
      LAYER M3 ;
        RECT  10.908 17.136 10.926 17.28 ;
    END
  END o[112]
  PIN o[113]
    DIRECTION OUTPUT ;
    USE SIGNAL ;
    PORT
      LAYER M5 ;
        RECT  10.992 17.088 11.016 17.28 ;
    END
  END o[113]
  PIN o[114]
    DIRECTION OUTPUT ;
    USE SIGNAL ;
    PORT
      LAYER M3 ;
        RECT  11.088 17.136 11.106 17.28 ;
    END
  END o[114]
  PIN o[115]
    DIRECTION OUTPUT ;
    USE SIGNAL ;
    PORT
      LAYER M5 ;
        RECT  11.136 17.088 11.16 17.28 ;
    END
  END o[115]
  PIN o[116]
    DIRECTION OUTPUT ;
    USE SIGNAL ;
    PORT
      LAYER M3 ;
        RECT  11.232 17.136 11.25 17.28 ;
    END
  END o[116]
  PIN o[117]
    DIRECTION OUTPUT ;
    USE SIGNAL ;
    PORT
      LAYER M5 ;
        RECT  11.328 17.088 11.352 17.28 ;
    END
  END o[117]
  PIN o[118]
    DIRECTION OUTPUT ;
    USE SIGNAL ;
    PORT
      LAYER M3 ;
        RECT  11.376 17.136 11.394 17.28 ;
    END
  END o[118]
  PIN o[119]
    DIRECTION OUTPUT ;
    USE SIGNAL ;
    PORT
      LAYER M5 ;
        RECT  11.472 17.088 11.496 17.28 ;
    END
  END o[119]
  PIN o[11]
    DIRECTION OUTPUT ;
    USE SIGNAL ;
    PORT
      LAYER M5 ;
        RECT  3.024 17.088 3.048 17.28 ;
    END
  END o[11]
  PIN o[120]
    DIRECTION OUTPUT ;
    USE SIGNAL ;
    PORT
      LAYER M3 ;
        RECT  11.556 17.136 11.574 17.28 ;
    END
  END o[120]
  PIN o[121]
    DIRECTION OUTPUT ;
    USE SIGNAL ;
    PORT
      LAYER M5 ;
        RECT  11.616 17.088 11.64 17.28 ;
    END
  END o[121]
  PIN o[122]
    DIRECTION OUTPUT ;
    USE SIGNAL ;
    PORT
      LAYER M3 ;
        RECT  11.7 17.136 11.718 17.28 ;
    END
  END o[122]
  PIN o[123]
    DIRECTION OUTPUT ;
    USE SIGNAL ;
    PORT
      LAYER M5 ;
        RECT  11.76 17.088 11.784 17.28 ;
    END
  END o[123]
  PIN o[124]
    DIRECTION OUTPUT ;
    USE SIGNAL ;
    PORT
      LAYER M3 ;
        RECT  11.844 17.136 11.862 17.28 ;
    END
  END o[124]
  PIN o[125]
    DIRECTION OUTPUT ;
    USE SIGNAL ;
    PORT
      LAYER M5 ;
        RECT  11.952 17.088 11.976 17.28 ;
    END
  END o[125]
  PIN o[126]
    DIRECTION OUTPUT ;
    USE SIGNAL ;
    PORT
      LAYER M3 ;
        RECT  12.024 17.136 12.042 17.28 ;
    END
  END o[126]
  PIN o[127]
    DIRECTION OUTPUT ;
    USE SIGNAL ;
    PORT
      LAYER M5 ;
        RECT  12.096 17.088 12.12 17.28 ;
    END
  END o[127]
  PIN o[128]
    DIRECTION OUTPUT ;
    USE SIGNAL ;
    PORT
      LAYER M3 ;
        RECT  12.168 17.136 12.186 17.28 ;
    END
  END o[128]
  PIN o[129]
    DIRECTION OUTPUT ;
    USE SIGNAL ;
    PORT
      LAYER M5 ;
        RECT  12.24 17.088 12.264 17.28 ;
    END
  END o[129]
  PIN o[12]
    DIRECTION OUTPUT ;
    USE SIGNAL ;
    PORT
      LAYER M3 ;
        RECT  3.132 17.136 3.15 17.28 ;
    END
  END o[12]
  PIN o[130]
    DIRECTION OUTPUT ;
    USE SIGNAL ;
    PORT
      LAYER M3 ;
        RECT  12.312 17.136 12.33 17.28 ;
    END
  END o[130]
  PIN o[131]
    DIRECTION OUTPUT ;
    USE SIGNAL ;
    PORT
      LAYER M5 ;
        RECT  12.384 17.088 12.408 17.28 ;
    END
  END o[131]
  PIN o[132]
    DIRECTION OUTPUT ;
    USE SIGNAL ;
    PORT
      LAYER M3 ;
        RECT  12.492 17.136 12.51 17.28 ;
    END
  END o[132]
  PIN o[133]
    DIRECTION OUTPUT ;
    USE SIGNAL ;
    PORT
      LAYER M5 ;
        RECT  12.576 17.088 12.6 17.28 ;
    END
  END o[133]
  PIN o[134]
    DIRECTION OUTPUT ;
    USE SIGNAL ;
    PORT
      LAYER M3 ;
        RECT  12.636 17.136 12.654 17.28 ;
    END
  END o[134]
  PIN o[135]
    DIRECTION OUTPUT ;
    USE SIGNAL ;
    PORT
      LAYER M5 ;
        RECT  12.72 17.088 12.744 17.28 ;
    END
  END o[135]
  PIN o[136]
    DIRECTION OUTPUT ;
    USE SIGNAL ;
    PORT
      LAYER M3 ;
        RECT  12.78 17.136 12.798 17.28 ;
    END
  END o[136]
  PIN o[137]
    DIRECTION OUTPUT ;
    USE SIGNAL ;
    PORT
      LAYER M5 ;
        RECT  12.864 17.088 12.888 17.28 ;
    END
  END o[137]
  PIN o[138]
    DIRECTION OUTPUT ;
    USE SIGNAL ;
    PORT
      LAYER M5 ;
        RECT  13.008 17.088 13.032 17.28 ;
    END
  END o[138]
  PIN o[139]
    DIRECTION OUTPUT ;
    USE SIGNAL ;
    PORT
      LAYER M3 ;
        RECT  13.104 17.136 13.122 17.28 ;
    END
  END o[139]
  PIN o[13]
    DIRECTION OUTPUT ;
    USE SIGNAL ;
    PORT
      LAYER M5 ;
        RECT  3.216 17.088 3.24 17.28 ;
    END
  END o[13]
  PIN o[140]
    DIRECTION OUTPUT ;
    USE SIGNAL ;
    PORT
      LAYER M5 ;
        RECT  13.2 17.088 13.224 17.28 ;
    END
  END o[140]
  PIN o[141]
    DIRECTION OUTPUT ;
    USE SIGNAL ;
    PORT
      LAYER M3 ;
        RECT  13.248 17.136 13.266 17.28 ;
    END
  END o[141]
  PIN o[142]
    DIRECTION OUTPUT ;
    USE SIGNAL ;
    PORT
      LAYER M5 ;
        RECT  13.344 17.088 13.368 17.28 ;
    END
  END o[142]
  PIN o[143]
    DIRECTION OUTPUT ;
    USE SIGNAL ;
    PORT
      LAYER M3 ;
        RECT  13.428 17.136 13.446 17.28 ;
    END
  END o[143]
  PIN o[144]
    DIRECTION OUTPUT ;
    USE SIGNAL ;
    PORT
      LAYER M5 ;
        RECT  13.488 17.088 13.512 17.28 ;
    END
  END o[144]
  PIN o[145]
    DIRECTION OUTPUT ;
    USE SIGNAL ;
    PORT
      LAYER M3 ;
        RECT  13.572 17.136 13.59 17.28 ;
    END
  END o[145]
  PIN o[146]
    DIRECTION OUTPUT ;
    USE SIGNAL ;
    PORT
      LAYER M5 ;
        RECT  13.632 17.088 13.656 17.28 ;
    END
  END o[146]
  PIN o[147]
    DIRECTION OUTPUT ;
    USE SIGNAL ;
    PORT
      LAYER M3 ;
        RECT  13.716 17.136 13.734 17.28 ;
    END
  END o[147]
  PIN o[148]
    DIRECTION OUTPUT ;
    USE SIGNAL ;
    PORT
      LAYER M5 ;
        RECT  13.824 17.088 13.848 17.28 ;
    END
  END o[148]
  PIN o[149]
    DIRECTION OUTPUT ;
    USE SIGNAL ;
    PORT
      LAYER M3 ;
        RECT  13.896 17.136 13.914 17.28 ;
    END
  END o[149]
  PIN o[14]
    DIRECTION OUTPUT ;
    USE SIGNAL ;
    PORT
      LAYER M3 ;
        RECT  3.276 17.136 3.294 17.28 ;
    END
  END o[14]
  PIN o[150]
    DIRECTION OUTPUT ;
    USE SIGNAL ;
    PORT
      LAYER M5 ;
        RECT  13.968 17.088 13.992 17.28 ;
    END
  END o[150]
  PIN o[151]
    DIRECTION OUTPUT ;
    USE SIGNAL ;
    PORT
      LAYER M3 ;
        RECT  14.04 17.136 14.058 17.28 ;
    END
  END o[151]
  PIN o[152]
    DIRECTION OUTPUT ;
    USE SIGNAL ;
    PORT
      LAYER M5 ;
        RECT  14.112 17.088 14.136 17.28 ;
    END
  END o[152]
  PIN o[153]
    DIRECTION OUTPUT ;
    USE SIGNAL ;
    PORT
      LAYER M3 ;
        RECT  14.184 17.136 14.202 17.28 ;
    END
  END o[153]
  PIN o[154]
    DIRECTION OUTPUT ;
    USE SIGNAL ;
    PORT
      LAYER M5 ;
        RECT  14.256 17.088 14.28 17.28 ;
    END
  END o[154]
  PIN o[155]
    DIRECTION OUTPUT ;
    USE SIGNAL ;
    PORT
      LAYER M3 ;
        RECT  14.364 17.136 14.382 17.28 ;
    END
  END o[155]
  PIN o[156]
    DIRECTION OUTPUT ;
    USE SIGNAL ;
    PORT
      LAYER M5 ;
        RECT  14.448 17.088 14.472 17.28 ;
    END
  END o[156]
  PIN o[157]
    DIRECTION OUTPUT ;
    USE SIGNAL ;
    PORT
      LAYER M3 ;
        RECT  14.508 17.136 14.526 17.28 ;
    END
  END o[157]
  PIN o[158]
    DIRECTION OUTPUT ;
    USE SIGNAL ;
    PORT
      LAYER M5 ;
        RECT  14.592 17.088 14.616 17.28 ;
    END
  END o[158]
  PIN o[159]
    DIRECTION OUTPUT ;
    USE SIGNAL ;
    PORT
      LAYER M3 ;
        RECT  14.652 17.136 14.67 17.28 ;
    END
  END o[159]
  PIN o[15]
    DIRECTION OUTPUT ;
    USE SIGNAL ;
    PORT
      LAYER M5 ;
        RECT  3.36 17.088 3.384 17.28 ;
    END
  END o[15]
  PIN o[160]
    DIRECTION OUTPUT ;
    USE SIGNAL ;
    PORT
      LAYER M5 ;
        RECT  14.736 17.088 14.76 17.28 ;
    END
  END o[160]
  PIN o[161]
    DIRECTION OUTPUT ;
    USE SIGNAL ;
    PORT
      LAYER M3 ;
        RECT  14.832 17.136 14.85 17.28 ;
    END
  END o[161]
  PIN o[162]
    DIRECTION OUTPUT ;
    USE SIGNAL ;
    PORT
      LAYER M5 ;
        RECT  14.88 17.088 14.904 17.28 ;
    END
  END o[162]
  PIN o[163]
    DIRECTION OUTPUT ;
    USE SIGNAL ;
    PORT
      LAYER M3 ;
        RECT  14.976 17.136 14.994 17.28 ;
    END
  END o[163]
  PIN o[164]
    DIRECTION OUTPUT ;
    USE SIGNAL ;
    PORT
      LAYER M5 ;
        RECT  15.072 17.088 15.096 17.28 ;
    END
  END o[164]
  PIN o[165]
    DIRECTION OUTPUT ;
    USE SIGNAL ;
    PORT
      LAYER M3 ;
        RECT  15.12 17.136 15.138 17.28 ;
    END
  END o[165]
  PIN o[166]
    DIRECTION OUTPUT ;
    USE SIGNAL ;
    PORT
      LAYER M5 ;
        RECT  15.216 17.088 15.24 17.28 ;
    END
  END o[166]
  PIN o[167]
    DIRECTION OUTPUT ;
    USE SIGNAL ;
    PORT
      LAYER M3 ;
        RECT  15.3 17.136 15.318 17.28 ;
    END
  END o[167]
  PIN o[168]
    DIRECTION OUTPUT ;
    USE SIGNAL ;
    PORT
      LAYER M5 ;
        RECT  15.36 17.088 15.384 17.28 ;
    END
  END o[168]
  PIN o[169]
    DIRECTION OUTPUT ;
    USE SIGNAL ;
    PORT
      LAYER M3 ;
        RECT  15.444 17.136 15.462 17.28 ;
    END
  END o[169]
  PIN o[16]
    DIRECTION OUTPUT ;
    USE SIGNAL ;
    PORT
      LAYER M3 ;
        RECT  3.42 17.136 3.438 17.28 ;
    END
  END o[16]
  PIN o[170]
    DIRECTION OUTPUT ;
    USE SIGNAL ;
    PORT
      LAYER M5 ;
        RECT  15.504 17.088 15.528 17.28 ;
    END
  END o[170]
  PIN o[171]
    DIRECTION OUTPUT ;
    USE SIGNAL ;
    PORT
      LAYER M3 ;
        RECT  15.588 17.136 15.606 17.28 ;
    END
  END o[171]
  PIN o[172]
    DIRECTION OUTPUT ;
    USE SIGNAL ;
    PORT
      LAYER M5 ;
        RECT  15.696 17.088 15.72 17.28 ;
    END
  END o[172]
  PIN o[173]
    DIRECTION OUTPUT ;
    USE SIGNAL ;
    PORT
      LAYER M3 ;
        RECT  15.768 17.136 15.786 17.28 ;
    END
  END o[173]
  PIN o[174]
    DIRECTION OUTPUT ;
    USE SIGNAL ;
    PORT
      LAYER M5 ;
        RECT  15.84 17.088 15.864 17.28 ;
    END
  END o[174]
  PIN o[175]
    DIRECTION OUTPUT ;
    USE SIGNAL ;
    PORT
      LAYER M3 ;
        RECT  15.912 17.136 15.93 17.28 ;
    END
  END o[175]
  PIN o[176]
    DIRECTION OUTPUT ;
    USE SIGNAL ;
    PORT
      LAYER M5 ;
        RECT  15.984 17.088 16.008 17.28 ;
    END
  END o[176]
  PIN o[177]
    DIRECTION OUTPUT ;
    USE SIGNAL ;
    PORT
      LAYER M3 ;
        RECT  16.056 17.136 16.074 17.28 ;
    END
  END o[177]
  PIN o[178]
    DIRECTION OUTPUT ;
    USE SIGNAL ;
    PORT
      LAYER M5 ;
        RECT  16.128 17.088 16.152 17.28 ;
    END
  END o[178]
  PIN o[179]
    DIRECTION OUTPUT ;
    USE SIGNAL ;
    PORT
      LAYER M3 ;
        RECT  16.236 17.136 16.254 17.28 ;
    END
  END o[179]
  PIN o[17]
    DIRECTION OUTPUT ;
    USE SIGNAL ;
    PORT
      LAYER M5 ;
        RECT  3.504 17.088 3.528 17.28 ;
    END
  END o[17]
  PIN o[180]
    DIRECTION OUTPUT ;
    USE SIGNAL ;
    PORT
      LAYER M5 ;
        RECT  16.32 17.088 16.344 17.28 ;
    END
  END o[180]
  PIN o[181]
    DIRECTION OUTPUT ;
    USE SIGNAL ;
    PORT
      LAYER M3 ;
        RECT  16.38 17.136 16.398 17.28 ;
    END
  END o[181]
  PIN o[182]
    DIRECTION OUTPUT ;
    USE SIGNAL ;
    PORT
      LAYER M5 ;
        RECT  16.464 17.088 16.488 17.28 ;
    END
  END o[182]
  PIN o[183]
    DIRECTION OUTPUT ;
    USE SIGNAL ;
    PORT
      LAYER M3 ;
        RECT  16.524 17.136 16.542 17.28 ;
    END
  END o[183]
  PIN o[184]
    DIRECTION OUTPUT ;
    USE SIGNAL ;
    PORT
      LAYER M5 ;
        RECT  16.608 17.088 16.632 17.28 ;
    END
  END o[184]
  PIN o[185]
    DIRECTION OUTPUT ;
    USE SIGNAL ;
    PORT
      LAYER M3 ;
        RECT  16.704 17.136 16.722 17.28 ;
    END
  END o[185]
  PIN o[186]
    DIRECTION OUTPUT ;
    USE SIGNAL ;
    PORT
      LAYER M5 ;
        RECT  16.752 17.088 16.776 17.28 ;
    END
  END o[186]
  PIN o[187]
    DIRECTION OUTPUT ;
    USE SIGNAL ;
    PORT
      LAYER M3 ;
        RECT  16.848 17.136 16.866 17.28 ;
    END
  END o[187]
  PIN o[188]
    DIRECTION OUTPUT ;
    USE SIGNAL ;
    PORT
      LAYER M5 ;
        RECT  16.944 17.088 16.968 17.28 ;
    END
  END o[188]
  PIN o[189]
    DIRECTION OUTPUT ;
    USE SIGNAL ;
    PORT
      LAYER M3 ;
        RECT  16.992 17.136 17.01 17.28 ;
    END
  END o[189]
  PIN o[18]
    DIRECTION OUTPUT ;
    USE SIGNAL ;
    PORT
      LAYER M3 ;
        RECT  3.6 17.136 3.618 17.28 ;
    END
  END o[18]
  PIN o[190]
    DIRECTION OUTPUT ;
    USE SIGNAL ;
    PORT
      LAYER M5 ;
        RECT  17.088 17.088 17.112 17.28 ;
    END
  END o[190]
  PIN o[191]
    DIRECTION OUTPUT ;
    USE SIGNAL ;
    PORT
      LAYER M3 ;
        RECT  17.172 17.136 17.19 17.28 ;
    END
  END o[191]
  PIN o[192]
    DIRECTION OUTPUT ;
    USE SIGNAL ;
    PORT
      LAYER M5 ;
        RECT  17.232 17.088 17.256 17.28 ;
    END
  END o[192]
  PIN o[193]
    DIRECTION OUTPUT ;
    USE SIGNAL ;
    PORT
      LAYER M3 ;
        RECT  17.316 17.136 17.334 17.28 ;
    END
  END o[193]
  PIN o[194]
    DIRECTION OUTPUT ;
    USE SIGNAL ;
    PORT
      LAYER M5 ;
        RECT  17.376 17.088 17.4 17.28 ;
    END
  END o[194]
  PIN o[195]
    DIRECTION OUTPUT ;
    USE SIGNAL ;
    PORT
      LAYER M3 ;
        RECT  17.46 17.136 17.478 17.28 ;
    END
  END o[195]
  PIN o[196]
    DIRECTION OUTPUT ;
    USE SIGNAL ;
    PORT
      LAYER M5 ;
        RECT  17.568 17.088 17.592 17.28 ;
    END
  END o[196]
  PIN o[197]
    DIRECTION OUTPUT ;
    USE SIGNAL ;
    PORT
      LAYER M3 ;
        RECT  17.64 17.136 17.658 17.28 ;
    END
  END o[197]
  PIN o[198]
    DIRECTION OUTPUT ;
    USE SIGNAL ;
    PORT
      LAYER M5 ;
        RECT  17.712 17.088 17.736 17.28 ;
    END
  END o[198]
  PIN o[199]
    DIRECTION OUTPUT ;
    USE SIGNAL ;
    PORT
      LAYER M3 ;
        RECT  17.784 17.136 17.802 17.28 ;
    END
  END o[199]
  PIN o[19]
    DIRECTION OUTPUT ;
    USE SIGNAL ;
    PORT
      LAYER M5 ;
        RECT  3.648 17.088 3.672 17.28 ;
    END
  END o[19]
  PIN o[1]
    DIRECTION OUTPUT ;
    USE SIGNAL ;
    PORT
      LAYER M5 ;
        RECT  2.256 17.088 2.28 17.28 ;
    END
  END o[1]
  PIN o[200]
    DIRECTION OUTPUT ;
    USE SIGNAL ;
    PORT
      LAYER M5 ;
        RECT  17.856 17.088 17.88 17.28 ;
    END
  END o[200]
  PIN o[201]
    DIRECTION OUTPUT ;
    USE SIGNAL ;
    PORT
      LAYER M3 ;
        RECT  17.928 17.136 17.946 17.28 ;
    END
  END o[201]
  PIN o[202]
    DIRECTION OUTPUT ;
    USE SIGNAL ;
    PORT
      LAYER M5 ;
        RECT  18 17.088 18.024 17.28 ;
    END
  END o[202]
  PIN o[203]
    DIRECTION OUTPUT ;
    USE SIGNAL ;
    PORT
      LAYER M3 ;
        RECT  18.108 17.136 18.126 17.28 ;
    END
  END o[203]
  PIN o[204]
    DIRECTION OUTPUT ;
    USE SIGNAL ;
    PORT
      LAYER M5 ;
        RECT  18.192 17.088 18.216 17.28 ;
    END
  END o[204]
  PIN o[205]
    DIRECTION OUTPUT ;
    USE SIGNAL ;
    PORT
      LAYER M3 ;
        RECT  18.252 17.136 18.27 17.28 ;
    END
  END o[205]
  PIN o[206]
    DIRECTION OUTPUT ;
    USE SIGNAL ;
    PORT
      LAYER M5 ;
        RECT  18.336 17.088 18.36 17.28 ;
    END
  END o[206]
  PIN o[207]
    DIRECTION OUTPUT ;
    USE SIGNAL ;
    PORT
      LAYER M3 ;
        RECT  18.396 17.136 18.414 17.28 ;
    END
  END o[207]
  PIN o[208]
    DIRECTION OUTPUT ;
    USE SIGNAL ;
    PORT
      LAYER M5 ;
        RECT  18.48 17.088 18.504 17.28 ;
    END
  END o[208]
  PIN o[209]
    DIRECTION OUTPUT ;
    USE SIGNAL ;
    PORT
      LAYER M3 ;
        RECT  18.576 17.136 18.594 17.28 ;
    END
  END o[209]
  PIN o[20]
    DIRECTION OUTPUT ;
    USE SIGNAL ;
    PORT
      LAYER M3 ;
        RECT  3.744 17.136 3.762 17.28 ;
    END
  END o[20]
  PIN o[210]
    DIRECTION OUTPUT ;
    USE SIGNAL ;
    PORT
      LAYER M5 ;
        RECT  18.624 17.088 18.648 17.28 ;
    END
  END o[210]
  PIN o[211]
    DIRECTION OUTPUT ;
    USE SIGNAL ;
    PORT
      LAYER M3 ;
        RECT  18.72 17.136 18.738 17.28 ;
    END
  END o[211]
  PIN o[212]
    DIRECTION OUTPUT ;
    USE SIGNAL ;
    PORT
      LAYER M5 ;
        RECT  18.816 17.088 18.84 17.28 ;
    END
  END o[212]
  PIN o[213]
    DIRECTION OUTPUT ;
    USE SIGNAL ;
    PORT
      LAYER M3 ;
        RECT  18.864 17.136 18.882 17.28 ;
    END
  END o[213]
  PIN o[214]
    DIRECTION OUTPUT ;
    USE SIGNAL ;
    PORT
      LAYER M5 ;
        RECT  18.96 17.088 18.984 17.28 ;
    END
  END o[214]
  PIN o[215]
    DIRECTION OUTPUT ;
    USE SIGNAL ;
    PORT
      LAYER M3 ;
        RECT  19.044 17.136 19.062 17.28 ;
    END
  END o[215]
  PIN o[216]
    DIRECTION OUTPUT ;
    USE SIGNAL ;
    PORT
      LAYER M5 ;
        RECT  19.104 17.088 19.128 17.28 ;
    END
  END o[216]
  PIN o[217]
    DIRECTION OUTPUT ;
    USE SIGNAL ;
    PORT
      LAYER M3 ;
        RECT  19.188 17.136 19.206 17.28 ;
    END
  END o[217]
  PIN o[218]
    DIRECTION OUTPUT ;
    USE SIGNAL ;
    PORT
      LAYER M5 ;
        RECT  19.248 17.088 19.272 17.28 ;
    END
  END o[218]
  PIN o[219]
    DIRECTION OUTPUT ;
    USE SIGNAL ;
    PORT
      LAYER M3 ;
        RECT  19.332 17.136 19.35 17.28 ;
    END
  END o[219]
  PIN o[21]
    DIRECTION OUTPUT ;
    USE SIGNAL ;
    PORT
      LAYER M5 ;
        RECT  3.84 17.088 3.864 17.28 ;
    END
  END o[21]
  PIN o[220]
    DIRECTION OUTPUT ;
    USE SIGNAL ;
    PORT
      LAYER M5 ;
        RECT  19.44 17.088 19.464 17.28 ;
    END
  END o[220]
  PIN o[221]
    DIRECTION OUTPUT ;
    USE SIGNAL ;
    PORT
      LAYER M3 ;
        RECT  19.512 17.136 19.53 17.28 ;
    END
  END o[221]
  PIN o[222]
    DIRECTION OUTPUT ;
    USE SIGNAL ;
    PORT
      LAYER M5 ;
        RECT  19.584 17.088 19.608 17.28 ;
    END
  END o[222]
  PIN o[223]
    DIRECTION OUTPUT ;
    USE SIGNAL ;
    PORT
      LAYER M3 ;
        RECT  19.656 17.136 19.674 17.28 ;
    END
  END o[223]
  PIN o[224]
    DIRECTION OUTPUT ;
    USE SIGNAL ;
    PORT
      LAYER M5 ;
        RECT  19.728 17.088 19.752 17.28 ;
    END
  END o[224]
  PIN o[225]
    DIRECTION OUTPUT ;
    USE SIGNAL ;
    PORT
      LAYER M3 ;
        RECT  19.8 17.136 19.818 17.28 ;
    END
  END o[225]
  PIN o[226]
    DIRECTION OUTPUT ;
    USE SIGNAL ;
    PORT
      LAYER M5 ;
        RECT  19.872 17.088 19.896 17.28 ;
    END
  END o[226]
  PIN o[227]
    DIRECTION OUTPUT ;
    USE SIGNAL ;
    PORT
      LAYER M3 ;
        RECT  19.98 17.136 19.998 17.28 ;
    END
  END o[227]
  PIN o[228]
    DIRECTION OUTPUT ;
    USE SIGNAL ;
    PORT
      LAYER M5 ;
        RECT  20.064 17.088 20.088 17.28 ;
    END
  END o[228]
  PIN o[229]
    DIRECTION OUTPUT ;
    USE SIGNAL ;
    PORT
      LAYER M3 ;
        RECT  20.124 17.136 20.142 17.28 ;
    END
  END o[229]
  PIN o[22]
    DIRECTION OUTPUT ;
    USE SIGNAL ;
    PORT
      LAYER M3 ;
        RECT  3.888 17.136 3.906 17.28 ;
    END
  END o[22]
  PIN o[230]
    DIRECTION OUTPUT ;
    USE SIGNAL ;
    PORT
      LAYER M5 ;
        RECT  20.208 17.088 20.232 17.28 ;
    END
  END o[230]
  PIN o[231]
    DIRECTION OUTPUT ;
    USE SIGNAL ;
    PORT
      LAYER M3 ;
        RECT  20.268 17.136 20.286 17.28 ;
    END
  END o[231]
  PIN o[232]
    DIRECTION OUTPUT ;
    USE SIGNAL ;
    PORT
      LAYER M5 ;
        RECT  20.352 17.088 20.376 17.28 ;
    END
  END o[232]
  PIN o[233]
    DIRECTION OUTPUT ;
    USE SIGNAL ;
    PORT
      LAYER M3 ;
        RECT  20.448 17.136 20.466 17.28 ;
    END
  END o[233]
  PIN o[234]
    DIRECTION OUTPUT ;
    USE SIGNAL ;
    PORT
      LAYER M5 ;
        RECT  20.496 17.088 20.52 17.28 ;
    END
  END o[234]
  PIN o[235]
    DIRECTION OUTPUT ;
    USE SIGNAL ;
    PORT
      LAYER M3 ;
        RECT  20.592 17.136 20.61 17.28 ;
    END
  END o[235]
  PIN o[236]
    DIRECTION OUTPUT ;
    USE SIGNAL ;
    PORT
      LAYER M5 ;
        RECT  20.688 17.088 20.712 17.28 ;
    END
  END o[236]
  PIN o[237]
    DIRECTION OUTPUT ;
    USE SIGNAL ;
    PORT
      LAYER M3 ;
        RECT  20.736 17.136 20.754 17.28 ;
    END
  END o[237]
  PIN o[238]
    DIRECTION OUTPUT ;
    USE SIGNAL ;
    PORT
      LAYER M5 ;
        RECT  20.832 17.088 20.856 17.28 ;
    END
  END o[238]
  PIN o[239]
    DIRECTION OUTPUT ;
    USE SIGNAL ;
    PORT
      LAYER M3 ;
        RECT  20.916 17.136 20.934 17.28 ;
    END
  END o[239]
  PIN o[23]
    DIRECTION OUTPUT ;
    USE SIGNAL ;
    PORT
      LAYER M5 ;
        RECT  3.984 17.088 4.008 17.28 ;
    END
  END o[23]
  PIN o[240]
    DIRECTION OUTPUT ;
    USE SIGNAL ;
    PORT
      LAYER M5 ;
        RECT  20.976 17.088 21 17.28 ;
    END
  END o[240]
  PIN o[241]
    DIRECTION OUTPUT ;
    USE SIGNAL ;
    PORT
      LAYER M3 ;
        RECT  21.06 17.136 21.078 17.28 ;
    END
  END o[241]
  PIN o[242]
    DIRECTION OUTPUT ;
    USE SIGNAL ;
    PORT
      LAYER M5 ;
        RECT  21.12 17.088 21.144 17.28 ;
    END
  END o[242]
  PIN o[243]
    DIRECTION OUTPUT ;
    USE SIGNAL ;
    PORT
      LAYER M3 ;
        RECT  21.204 17.136 21.222 17.28 ;
    END
  END o[243]
  PIN o[244]
    DIRECTION OUTPUT ;
    USE SIGNAL ;
    PORT
      LAYER M5 ;
        RECT  21.312 17.088 21.336 17.28 ;
    END
  END o[244]
  PIN o[245]
    DIRECTION OUTPUT ;
    USE SIGNAL ;
    PORT
      LAYER M3 ;
        RECT  21.384 17.136 21.402 17.28 ;
    END
  END o[245]
  PIN o[246]
    DIRECTION OUTPUT ;
    USE SIGNAL ;
    PORT
      LAYER M5 ;
        RECT  21.456 17.088 21.48 17.28 ;
    END
  END o[246]
  PIN o[247]
    DIRECTION OUTPUT ;
    USE SIGNAL ;
    PORT
      LAYER M3 ;
        RECT  21.528 17.136 21.546 17.28 ;
    END
  END o[247]
  PIN o[248]
    DIRECTION OUTPUT ;
    USE SIGNAL ;
    PORT
      LAYER M5 ;
        RECT  21.6 17.088 21.624 17.28 ;
    END
  END o[248]
  PIN o[249]
    DIRECTION OUTPUT ;
    USE SIGNAL ;
    PORT
      LAYER M3 ;
        RECT  21.672 17.136 21.69 17.28 ;
    END
  END o[249]
  PIN o[24]
    DIRECTION OUTPUT ;
    USE SIGNAL ;
    PORT
      LAYER M3 ;
        RECT  4.068 17.136 4.086 17.28 ;
    END
  END o[24]
  PIN o[250]
    DIRECTION OUTPUT ;
    USE SIGNAL ;
    PORT
      LAYER M5 ;
        RECT  21.744 17.088 21.768 17.28 ;
    END
  END o[250]
  PIN o[251]
    DIRECTION OUTPUT ;
    USE SIGNAL ;
    PORT
      LAYER M3 ;
        RECT  21.852 17.136 21.87 17.28 ;
    END
  END o[251]
  PIN o[252]
    DIRECTION OUTPUT ;
    USE SIGNAL ;
    PORT
      LAYER M5 ;
        RECT  21.936 17.088 21.96 17.28 ;
    END
  END o[252]
  PIN o[253]
    DIRECTION OUTPUT ;
    USE SIGNAL ;
    PORT
      LAYER M3 ;
        RECT  21.996 17.136 22.014 17.28 ;
    END
  END o[253]
  PIN o[254]
    DIRECTION OUTPUT ;
    USE SIGNAL ;
    PORT
      LAYER M5 ;
        RECT  22.08 17.088 22.104 17.28 ;
    END
  END o[254]
  PIN o[255]
    DIRECTION OUTPUT ;
    USE SIGNAL ;
    PORT
      LAYER M3 ;
        RECT  22.14 17.136 22.158 17.28 ;
    END
  END o[255]
  PIN o[256]
    DIRECTION OUTPUT ;
    USE SIGNAL ;
    PORT
      LAYER M5 ;
        RECT  22.224 17.088 22.248 17.28 ;
    END
  END o[256]
  PIN o[257]
    DIRECTION OUTPUT ;
    USE SIGNAL ;
    PORT
      LAYER M3 ;
        RECT  22.32 17.136 22.338 17.28 ;
    END
  END o[257]
  PIN o[258]
    DIRECTION OUTPUT ;
    USE SIGNAL ;
    PORT
      LAYER M5 ;
        RECT  22.368 17.088 22.392 17.28 ;
    END
  END o[258]
  PIN o[259]
    DIRECTION OUTPUT ;
    USE SIGNAL ;
    PORT
      LAYER M3 ;
        RECT  22.464 17.136 22.482 17.28 ;
    END
  END o[259]
  PIN o[25]
    DIRECTION OUTPUT ;
    USE SIGNAL ;
    PORT
      LAYER M5 ;
        RECT  4.128 17.088 4.152 17.28 ;
    END
  END o[25]
  PIN o[260]
    DIRECTION OUTPUT ;
    USE SIGNAL ;
    PORT
      LAYER M5 ;
        RECT  22.56 17.088 22.584 17.28 ;
    END
  END o[260]
  PIN o[261]
    DIRECTION OUTPUT ;
    USE SIGNAL ;
    PORT
      LAYER M3 ;
        RECT  22.608 17.136 22.626 17.28 ;
    END
  END o[261]
  PIN o[262]
    DIRECTION OUTPUT ;
    USE SIGNAL ;
    PORT
      LAYER M5 ;
        RECT  22.704 17.088 22.728 17.28 ;
    END
  END o[262]
  PIN o[263]
    DIRECTION OUTPUT ;
    USE SIGNAL ;
    PORT
      LAYER M3 ;
        RECT  22.788 17.136 22.806 17.28 ;
    END
  END o[263]
  PIN o[264]
    DIRECTION OUTPUT ;
    USE SIGNAL ;
    PORT
      LAYER M5 ;
        RECT  22.848 17.088 22.872 17.28 ;
    END
  END o[264]
  PIN o[265]
    DIRECTION OUTPUT ;
    USE SIGNAL ;
    PORT
      LAYER M3 ;
        RECT  22.932 17.136 22.95 17.28 ;
    END
  END o[265]
  PIN o[266]
    DIRECTION OUTPUT ;
    USE SIGNAL ;
    PORT
      LAYER M5 ;
        RECT  22.992 17.088 23.016 17.28 ;
    END
  END o[266]
  PIN o[267]
    DIRECTION OUTPUT ;
    USE SIGNAL ;
    PORT
      LAYER M3 ;
        RECT  23.076 17.136 23.094 17.28 ;
    END
  END o[267]
  PIN o[268]
    DIRECTION OUTPUT ;
    USE SIGNAL ;
    PORT
      LAYER M5 ;
        RECT  23.184 17.088 23.208 17.28 ;
    END
  END o[268]
  PIN o[269]
    DIRECTION OUTPUT ;
    USE SIGNAL ;
    PORT
      LAYER M3 ;
        RECT  23.256 17.136 23.274 17.28 ;
    END
  END o[269]
  PIN o[26]
    DIRECTION OUTPUT ;
    USE SIGNAL ;
    PORT
      LAYER M3 ;
        RECT  4.212 17.136 4.23 17.28 ;
    END
  END o[26]
  PIN o[270]
    DIRECTION OUTPUT ;
    USE SIGNAL ;
    PORT
      LAYER M5 ;
        RECT  23.328 17.088 23.352 17.28 ;
    END
  END o[270]
  PIN o[271]
    DIRECTION OUTPUT ;
    USE SIGNAL ;
    PORT
      LAYER M3 ;
        RECT  23.4 17.136 23.418 17.28 ;
    END
  END o[271]
  PIN o[272]
    DIRECTION OUTPUT ;
    USE SIGNAL ;
    PORT
      LAYER M5 ;
        RECT  23.472 17.088 23.496 17.28 ;
    END
  END o[272]
  PIN o[273]
    DIRECTION OUTPUT ;
    USE SIGNAL ;
    PORT
      LAYER M3 ;
        RECT  23.544 17.136 23.562 17.28 ;
    END
  END o[273]
  PIN o[274]
    DIRECTION OUTPUT ;
    USE SIGNAL ;
    PORT
      LAYER M5 ;
        RECT  23.616 17.088 23.64 17.28 ;
    END
  END o[274]
  PIN o[275]
    DIRECTION OUTPUT ;
    USE SIGNAL ;
    PORT
      LAYER M3 ;
        RECT  23.724 17.136 23.742 17.28 ;
    END
  END o[275]
  PIN o[27]
    DIRECTION OUTPUT ;
    USE SIGNAL ;
    PORT
      LAYER M5 ;
        RECT  4.272 17.088 4.296 17.28 ;
    END
  END o[27]
  PIN o[28]
    DIRECTION OUTPUT ;
    USE SIGNAL ;
    PORT
      LAYER M3 ;
        RECT  4.356 17.136 4.374 17.28 ;
    END
  END o[28]
  PIN o[29]
    DIRECTION OUTPUT ;
    USE SIGNAL ;
    PORT
      LAYER M5 ;
        RECT  4.464 17.088 4.488 17.28 ;
    END
  END o[29]
  PIN o[2]
    DIRECTION OUTPUT ;
    USE SIGNAL ;
    PORT
      LAYER M3 ;
        RECT  2.34 17.136 2.358 17.28 ;
    END
  END o[2]
  PIN o[30]
    DIRECTION OUTPUT ;
    USE SIGNAL ;
    PORT
      LAYER M3 ;
        RECT  4.536 17.136 4.554 17.28 ;
    END
  END o[30]
  PIN o[31]
    DIRECTION OUTPUT ;
    USE SIGNAL ;
    PORT
      LAYER M5 ;
        RECT  4.608 17.088 4.632 17.28 ;
    END
  END o[31]
  PIN o[32]
    DIRECTION OUTPUT ;
    USE SIGNAL ;
    PORT
      LAYER M3 ;
        RECT  4.68 17.136 4.698 17.28 ;
    END
  END o[32]
  PIN o[33]
    DIRECTION OUTPUT ;
    USE SIGNAL ;
    PORT
      LAYER M5 ;
        RECT  4.752 17.088 4.776 17.28 ;
    END
  END o[33]
  PIN o[34]
    DIRECTION OUTPUT ;
    USE SIGNAL ;
    PORT
      LAYER M3 ;
        RECT  4.824 17.136 4.842 17.28 ;
    END
  END o[34]
  PIN o[35]
    DIRECTION OUTPUT ;
    USE SIGNAL ;
    PORT
      LAYER M5 ;
        RECT  4.896 17.088 4.92 17.28 ;
    END
  END o[35]
  PIN o[36]
    DIRECTION OUTPUT ;
    USE SIGNAL ;
    PORT
      LAYER M3 ;
        RECT  5.004 17.136 5.022 17.28 ;
    END
  END o[36]
  PIN o[37]
    DIRECTION OUTPUT ;
    USE SIGNAL ;
    PORT
      LAYER M5 ;
        RECT  5.088 17.088 5.112 17.28 ;
    END
  END o[37]
  PIN o[38]
    DIRECTION OUTPUT ;
    USE SIGNAL ;
    PORT
      LAYER M3 ;
        RECT  5.148 17.136 5.166 17.28 ;
    END
  END o[38]
  PIN o[39]
    DIRECTION OUTPUT ;
    USE SIGNAL ;
    PORT
      LAYER M5 ;
        RECT  5.232 17.088 5.256 17.28 ;
    END
  END o[39]
  PIN o[3]
    DIRECTION OUTPUT ;
    USE SIGNAL ;
    PORT
      LAYER M5 ;
        RECT  2.4 17.088 2.424 17.28 ;
    END
  END o[3]
  PIN o[40]
    DIRECTION OUTPUT ;
    USE SIGNAL ;
    PORT
      LAYER M3 ;
        RECT  5.292 17.136 5.31 17.28 ;
    END
  END o[40]
  PIN o[41]
    DIRECTION OUTPUT ;
    USE SIGNAL ;
    PORT
      LAYER M5 ;
        RECT  5.376 17.088 5.4 17.28 ;
    END
  END o[41]
  PIN o[42]
    DIRECTION OUTPUT ;
    USE SIGNAL ;
    PORT
      LAYER M3 ;
        RECT  5.472 17.136 5.49 17.28 ;
    END
  END o[42]
  PIN o[43]
    DIRECTION OUTPUT ;
    USE SIGNAL ;
    PORT
      LAYER M5 ;
        RECT  5.52 17.088 5.544 17.28 ;
    END
  END o[43]
  PIN o[44]
    DIRECTION OUTPUT ;
    USE SIGNAL ;
    PORT
      LAYER M3 ;
        RECT  5.616 17.136 5.634 17.28 ;
    END
  END o[44]
  PIN o[45]
    DIRECTION OUTPUT ;
    USE SIGNAL ;
    PORT
      LAYER M5 ;
        RECT  5.712 17.088 5.736 17.28 ;
    END
  END o[45]
  PIN o[46]
    DIRECTION OUTPUT ;
    USE SIGNAL ;
    PORT
      LAYER M3 ;
        RECT  5.76 17.136 5.778 17.28 ;
    END
  END o[46]
  PIN o[47]
    DIRECTION OUTPUT ;
    USE SIGNAL ;
    PORT
      LAYER M5 ;
        RECT  5.856 17.088 5.88 17.28 ;
    END
  END o[47]
  PIN o[48]
    DIRECTION OUTPUT ;
    USE SIGNAL ;
    PORT
      LAYER M3 ;
        RECT  5.94 17.136 5.958 17.28 ;
    END
  END o[48]
  PIN o[49]
    DIRECTION OUTPUT ;
    USE SIGNAL ;
    PORT
      LAYER M5 ;
        RECT  6 17.088 6.024 17.28 ;
    END
  END o[49]
  PIN o[4]
    DIRECTION OUTPUT ;
    USE SIGNAL ;
    PORT
      LAYER M3 ;
        RECT  2.484 17.136 2.502 17.28 ;
    END
  END o[4]
  PIN o[50]
    DIRECTION OUTPUT ;
    USE SIGNAL ;
    PORT
      LAYER M3 ;
        RECT  6.084 17.136 6.102 17.28 ;
    END
  END o[50]
  PIN o[51]
    DIRECTION OUTPUT ;
    USE SIGNAL ;
    PORT
      LAYER M5 ;
        RECT  6.144 17.088 6.168 17.28 ;
    END
  END o[51]
  PIN o[52]
    DIRECTION OUTPUT ;
    USE SIGNAL ;
    PORT
      LAYER M3 ;
        RECT  6.228 17.136 6.246 17.28 ;
    END
  END o[52]
  PIN o[53]
    DIRECTION OUTPUT ;
    USE SIGNAL ;
    PORT
      LAYER M5 ;
        RECT  6.336 17.088 6.36 17.28 ;
    END
  END o[53]
  PIN o[54]
    DIRECTION OUTPUT ;
    USE SIGNAL ;
    PORT
      LAYER M3 ;
        RECT  6.408 17.136 6.426 17.28 ;
    END
  END o[54]
  PIN o[55]
    DIRECTION OUTPUT ;
    USE SIGNAL ;
    PORT
      LAYER M5 ;
        RECT  6.48 17.088 6.504 17.28 ;
    END
  END o[55]
  PIN o[56]
    DIRECTION OUTPUT ;
    USE SIGNAL ;
    PORT
      LAYER M3 ;
        RECT  6.552 17.136 6.57 17.28 ;
    END
  END o[56]
  PIN o[57]
    DIRECTION OUTPUT ;
    USE SIGNAL ;
    PORT
      LAYER M5 ;
        RECT  6.624 17.088 6.648 17.28 ;
    END
  END o[57]
  PIN o[58]
    DIRECTION OUTPUT ;
    USE SIGNAL ;
    PORT
      LAYER M3 ;
        RECT  6.696 17.136 6.714 17.28 ;
    END
  END o[58]
  PIN o[59]
    DIRECTION OUTPUT ;
    USE SIGNAL ;
    PORT
      LAYER M5 ;
        RECT  6.768 17.088 6.792 17.28 ;
    END
  END o[59]
  PIN o[5]
    DIRECTION OUTPUT ;
    USE SIGNAL ;
    PORT
      LAYER M5 ;
        RECT  2.592 17.088 2.616 17.28 ;
    END
  END o[5]
  PIN o[60]
    DIRECTION OUTPUT ;
    USE SIGNAL ;
    PORT
      LAYER M3 ;
        RECT  6.876 17.136 6.894 17.28 ;
    END
  END o[60]
  PIN o[61]
    DIRECTION OUTPUT ;
    USE SIGNAL ;
    PORT
      LAYER M5 ;
        RECT  6.96 17.088 6.984 17.28 ;
    END
  END o[61]
  PIN o[62]
    DIRECTION OUTPUT ;
    USE SIGNAL ;
    PORT
      LAYER M3 ;
        RECT  7.02 17.136 7.038 17.28 ;
    END
  END o[62]
  PIN o[63]
    DIRECTION OUTPUT ;
    USE SIGNAL ;
    PORT
      LAYER M5 ;
        RECT  7.104 17.088 7.128 17.28 ;
    END
  END o[63]
  PIN o[64]
    DIRECTION OUTPUT ;
    USE SIGNAL ;
    PORT
      LAYER M3 ;
        RECT  7.164 17.136 7.182 17.28 ;
    END
  END o[64]
  PIN o[65]
    DIRECTION OUTPUT ;
    USE SIGNAL ;
    PORT
      LAYER M5 ;
        RECT  7.248 17.088 7.272 17.28 ;
    END
  END o[65]
  PIN o[66]
    DIRECTION OUTPUT ;
    USE SIGNAL ;
    PORT
      LAYER M3 ;
        RECT  7.344 17.136 7.362 17.28 ;
    END
  END o[66]
  PIN o[67]
    DIRECTION OUTPUT ;
    USE SIGNAL ;
    PORT
      LAYER M5 ;
        RECT  7.392 17.088 7.416 17.28 ;
    END
  END o[67]
  PIN o[68]
    DIRECTION OUTPUT ;
    USE SIGNAL ;
    PORT
      LAYER M3 ;
        RECT  7.488 17.136 7.506 17.28 ;
    END
  END o[68]
  PIN o[69]
    DIRECTION OUTPUT ;
    USE SIGNAL ;
    PORT
      LAYER M5 ;
        RECT  7.584 17.088 7.608 17.28 ;
    END
  END o[69]
  PIN o[6]
    DIRECTION OUTPUT ;
    USE SIGNAL ;
    PORT
      LAYER M3 ;
        RECT  2.664 17.136 2.682 17.28 ;
    END
  END o[6]
  PIN o[70]
    DIRECTION OUTPUT ;
    USE SIGNAL ;
    PORT
      LAYER M3 ;
        RECT  7.632 17.136 7.65 17.28 ;
    END
  END o[70]
  PIN o[71]
    DIRECTION OUTPUT ;
    USE SIGNAL ;
    PORT
      LAYER M5 ;
        RECT  7.728 17.088 7.752 17.28 ;
    END
  END o[71]
  PIN o[72]
    DIRECTION OUTPUT ;
    USE SIGNAL ;
    PORT
      LAYER M3 ;
        RECT  7.812 17.136 7.83 17.28 ;
    END
  END o[72]
  PIN o[73]
    DIRECTION OUTPUT ;
    USE SIGNAL ;
    PORT
      LAYER M5 ;
        RECT  7.872 17.088 7.896 17.28 ;
    END
  END o[73]
  PIN o[74]
    DIRECTION OUTPUT ;
    USE SIGNAL ;
    PORT
      LAYER M3 ;
        RECT  7.956 17.136 7.974 17.28 ;
    END
  END o[74]
  PIN o[75]
    DIRECTION OUTPUT ;
    USE SIGNAL ;
    PORT
      LAYER M5 ;
        RECT  8.016 17.088 8.04 17.28 ;
    END
  END o[75]
  PIN o[76]
    DIRECTION OUTPUT ;
    USE SIGNAL ;
    PORT
      LAYER M3 ;
        RECT  8.1 17.136 8.118 17.28 ;
    END
  END o[76]
  PIN o[77]
    DIRECTION OUTPUT ;
    USE SIGNAL ;
    PORT
      LAYER M5 ;
        RECT  8.208 17.088 8.232 17.28 ;
    END
  END o[77]
  PIN o[78]
    DIRECTION OUTPUT ;
    USE SIGNAL ;
    PORT
      LAYER M3 ;
        RECT  8.28 17.136 8.298 17.28 ;
    END
  END o[78]
  PIN o[79]
    DIRECTION OUTPUT ;
    USE SIGNAL ;
    PORT
      LAYER M5 ;
        RECT  8.352 17.088 8.376 17.28 ;
    END
  END o[79]
  PIN o[7]
    DIRECTION OUTPUT ;
    USE SIGNAL ;
    PORT
      LAYER M5 ;
        RECT  2.736 17.088 2.76 17.28 ;
    END
  END o[7]
  PIN o[80]
    DIRECTION OUTPUT ;
    USE SIGNAL ;
    PORT
      LAYER M3 ;
        RECT  8.424 17.136 8.442 17.28 ;
    END
  END o[80]
  PIN o[81]
    DIRECTION OUTPUT ;
    USE SIGNAL ;
    PORT
      LAYER M5 ;
        RECT  8.496 17.088 8.52 17.28 ;
    END
  END o[81]
  PIN o[82]
    DIRECTION OUTPUT ;
    USE SIGNAL ;
    PORT
      LAYER M3 ;
        RECT  8.568 17.136 8.586 17.28 ;
    END
  END o[82]
  PIN o[83]
    DIRECTION OUTPUT ;
    USE SIGNAL ;
    PORT
      LAYER M5 ;
        RECT  8.64 17.088 8.664 17.28 ;
    END
  END o[83]
  PIN o[84]
    DIRECTION OUTPUT ;
    USE SIGNAL ;
    PORT
      LAYER M3 ;
        RECT  8.748 17.136 8.766 17.28 ;
    END
  END o[84]
  PIN o[85]
    DIRECTION OUTPUT ;
    USE SIGNAL ;
    PORT
      LAYER M5 ;
        RECT  8.832 17.088 8.856 17.28 ;
    END
  END o[85]
  PIN o[86]
    DIRECTION OUTPUT ;
    USE SIGNAL ;
    PORT
      LAYER M3 ;
        RECT  8.892 17.136 8.91 17.28 ;
    END
  END o[86]
  PIN o[87]
    DIRECTION OUTPUT ;
    USE SIGNAL ;
    PORT
      LAYER M5 ;
        RECT  8.976 17.088 9 17.28 ;
    END
  END o[87]
  PIN o[88]
    DIRECTION OUTPUT ;
    USE SIGNAL ;
    PORT
      LAYER M3 ;
        RECT  9.036 17.136 9.054 17.28 ;
    END
  END o[88]
  PIN o[89]
    DIRECTION OUTPUT ;
    USE SIGNAL ;
    PORT
      LAYER M5 ;
        RECT  9.12 17.088 9.144 17.28 ;
    END
  END o[89]
  PIN o[8]
    DIRECTION OUTPUT ;
    USE SIGNAL ;
    PORT
      LAYER M3 ;
        RECT  2.808 17.136 2.826 17.28 ;
    END
  END o[8]
  PIN o[90]
    DIRECTION OUTPUT ;
    USE SIGNAL ;
    PORT
      LAYER M3 ;
        RECT  9.216 17.136 9.234 17.28 ;
    END
  END o[90]
  PIN o[91]
    DIRECTION OUTPUT ;
    USE SIGNAL ;
    PORT
      LAYER M5 ;
        RECT  9.264 17.088 9.288 17.28 ;
    END
  END o[91]
  PIN o[92]
    DIRECTION OUTPUT ;
    USE SIGNAL ;
    PORT
      LAYER M3 ;
        RECT  9.36 17.136 9.378 17.28 ;
    END
  END o[92]
  PIN o[93]
    DIRECTION OUTPUT ;
    USE SIGNAL ;
    PORT
      LAYER M5 ;
        RECT  9.456 17.088 9.48 17.28 ;
    END
  END o[93]
  PIN o[94]
    DIRECTION OUTPUT ;
    USE SIGNAL ;
    PORT
      LAYER M3 ;
        RECT  9.504 17.136 9.522 17.28 ;
    END
  END o[94]
  PIN o[95]
    DIRECTION OUTPUT ;
    USE SIGNAL ;
    PORT
      LAYER M5 ;
        RECT  9.6 17.088 9.624 17.28 ;
    END
  END o[95]
  PIN o[96]
    DIRECTION OUTPUT ;
    USE SIGNAL ;
    PORT
      LAYER M3 ;
        RECT  9.684 17.136 9.702 17.28 ;
    END
  END o[96]
  PIN o[97]
    DIRECTION OUTPUT ;
    USE SIGNAL ;
    PORT
      LAYER M5 ;
        RECT  9.744 17.088 9.768 17.28 ;
    END
  END o[97]
  PIN o[98]
    DIRECTION OUTPUT ;
    USE SIGNAL ;
    PORT
      LAYER M3 ;
        RECT  9.828 17.136 9.846 17.28 ;
    END
  END o[98]
  PIN o[99]
    DIRECTION OUTPUT ;
    USE SIGNAL ;
    PORT
      LAYER M5 ;
        RECT  9.888 17.088 9.912 17.28 ;
    END
  END o[99]
  PIN o[9]
    DIRECTION OUTPUT ;
    USE SIGNAL ;
    PORT
      LAYER M5 ;
        RECT  2.88 17.088 2.904 17.28 ;
    END
  END o[9]
  PIN rs
    DIRECTION INPUT ;
    USE SIGNAL ;
    PORT
      LAYER M4 ;
        RECT  25.728 11.904 25.92 11.928 ;
    END
  END rs
  PIN VDD
    DIRECTION INOUT ;
    USE POWER ;
    PORT
      LAYER M5 ;
        RECT  21.492 2.151 21.612 15.129 ;
        RECT  18.792 2.151 18.912 15.129 ;
        RECT  16.092 2.151 16.212 15.129 ;
        RECT  13.392 2.151 13.512 15.129 ;
        RECT  10.692 2.151 10.812 15.129 ;
        RECT  7.992 2.151 8.112 15.129 ;
        RECT  5.292 2.151 5.412 15.129 ;
        RECT  2.592 2.151 2.712 15.129 ;
    END
  END VDD
  PIN VSS
    DIRECTION INOUT ;
    USE GROUND ;
    PORT
      LAYER M5 ;
        RECT  21.3 2.137 21.42 15.143 ;
        RECT  18.6 2.137 18.72 15.143 ;
        RECT  15.9 2.137 16.02 15.143 ;
        RECT  13.2 2.137 13.32 15.143 ;
        RECT  10.5 2.137 10.62 15.143 ;
        RECT  7.8 2.137 7.92 15.143 ;
        RECT  5.1 2.137 5.22 15.143 ;
        RECT  2.4 2.137 2.52 15.143 ;
    END
  END VSS
  OBS
    LAYER RVTN ;
     RECT  2.16 2.16 23.76 2.295 ;
     RECT  2.16 2.565 23.76 2.835 ;
     RECT  2.16 3.105 23.76 3.375 ;
     RECT  2.16 3.645 23.76 3.915 ;
     RECT  2.16 4.185 23.76 4.455 ;
     RECT  2.16 4.725 23.76 4.995 ;
     RECT  2.16 5.265 23.76 5.535 ;
     RECT  2.16 5.805 23.76 6.075 ;
     RECT  2.16 6.345 23.76 6.615 ;
     RECT  2.16 6.885 23.76 7.155 ;
     RECT  2.16 7.425 23.76 7.695 ;
     RECT  2.16 7.965 23.76 8.235 ;
     RECT  2.16 8.505 23.76 8.775 ;
     RECT  2.16 9.045 23.76 9.315 ;
     RECT  2.16 9.585 23.76 9.855 ;
     RECT  2.16 10.125 23.76 10.395 ;
     RECT  2.16 10.665 23.76 10.935 ;
     RECT  2.16 11.205 23.76 11.475 ;
     RECT  2.16 11.745 23.76 12.015 ;
     RECT  2.16 12.285 23.76 12.555 ;
     RECT  2.16 12.825 23.76 13.095 ;
     RECT  2.16 13.365 23.76 13.635 ;
     RECT  2.16 13.905 23.76 14.175 ;
     RECT  2.16 14.445 23.76 14.715 ;
     RECT  2.16 14.985 23.76 15.12 ;
    LAYER RVTP ;
     RECT  2.16 2.295 23.76 2.565 ;
     RECT  2.16 2.835 23.76 3.105 ;
     RECT  2.16 3.375 23.76 3.645 ;
     RECT  2.16 3.915 23.76 4.185 ;
     RECT  2.16 4.455 23.76 4.725 ;
     RECT  2.16 4.995 23.76 5.265 ;
     RECT  2.16 5.535 23.76 5.805 ;
     RECT  2.16 6.075 23.76 6.345 ;
     RECT  2.16 6.615 23.76 6.885 ;
     RECT  2.16 7.155 23.76 7.425 ;
     RECT  2.16 7.695 23.76 7.965 ;
     RECT  2.16 8.235 23.76 8.505 ;
     RECT  2.16 8.775 23.76 9.045 ;
     RECT  2.16 9.315 23.76 9.585 ;
     RECT  2.16 9.855 23.76 10.125 ;
     RECT  2.16 10.395 23.76 10.665 ;
     RECT  2.16 10.935 23.76 11.205 ;
     RECT  2.16 11.475 23.76 11.745 ;
     RECT  2.16 12.015 23.76 12.285 ;
     RECT  2.16 12.555 23.76 12.825 ;
     RECT  2.16 13.095 23.76 13.365 ;
     RECT  2.16 13.635 23.76 13.905 ;
     RECT  2.16 14.175 23.76 14.445 ;
     RECT  2.16 14.715 23.76 14.985 ;
    LAYER M1 ;
     RECT  2.16 2.151 23.76 15.129 ;
    LAYER M2 ;
     RECT  0.931 13.716 0.967 13.734 ;
     RECT  0.967 13.41 1.003 13.734 ;
     RECT  1.003 12.798 1.039 13.734 ;
     RECT  1.111 2.106 1.291 2.124 ;
     RECT  1.111 6.696 1.327 6.714 ;
     RECT  1.291 2.106 1.363 2.394 ;
     RECT  1.075 3.726 1.363 3.744 ;
     RECT  1.363 11.754 1.399 11.772 ;
     RECT  1.363 2.106 1.435 3.744 ;
     RECT  1.435 10.944 1.471 10.962 ;
     RECT  1.471 10.638 1.507 10.962 ;
     RECT  1.399 11.754 1.507 11.844 ;
     RECT  1.435 2.07 1.543 3.744 ;
     RECT  1.507 10.638 1.615 11.844 ;
     RECT  1.543 2.07 1.651 4.284 ;
     RECT  1.615 10.476 1.651 11.844 ;
     RECT  1.039 12.798 1.651 14.004 ;
     RECT  1.651 2.07 1.687 4.914 ;
     RECT  1.075 8.244 1.903 8.262 ;
     RECT  1.903 7.902 1.975 8.262 ;
     RECT  2.047 0.036 2.119 0.054 ;
     RECT  1.687 2.07 2.119 5.184 ;
     RECT  1.651 10.476 2.155 14.004 ;
     RECT  2.119 2.07 2.16 5.634 ;
     RECT  1.327 6.696 2.16 6.84 ;
     RECT  1.975 7.704 2.16 8.262 ;
     RECT  2.083 9.054 2.16 9.072 ;
     RECT  2.155 10.404 2.16 14.004 ;
     RECT  2.119 0.036 2.299 0.162 ;
     RECT  2.16 2.07 2.371 15.129 ;
     RECT  2.371 2.07 2.659 15.21 ;
     RECT  2.299 0.036 2.687 0.234 ;
     RECT  2.659 1.152 2.695 15.21 ;
     RECT  2.695 1.152 2.831 15.318 ;
     RECT  2.831 1.926 3.551 15.282 ;
     RECT  3.551 1.926 3.767 15.21 ;
     RECT  3.739 16.074 3.811 16.092 ;
     RECT  3.811 16.074 3.911 16.164 ;
     RECT  4.171 17.19 4.207 17.208 ;
     RECT  4.207 17.118 4.307 17.208 ;
     RECT  2.831 1.152 4.379 1.17 ;
     RECT  2.687 0.036 4.639 0.162 ;
     RECT  3.767 1.998 4.675 15.21 ;
     RECT  4.675 1.998 5.063 15.354 ;
     RECT  4.639 0.036 5.315 0.594 ;
     RECT  5.315 0.144 5.431 0.594 ;
     RECT  5.431 0.144 5.531 1.17 ;
     RECT  5.063 1.998 5.675 15.21 ;
     RECT  5.531 0.144 5.963 0.594 ;
     RECT  5.971 16.65 6.251 16.668 ;
     RECT  5.675 1.998 6.547 15.129 ;
     RECT  5.963 0.144 6.691 0.162 ;
     RECT  6.547 1.998 6.791 15.174 ;
     RECT  6.691 0.144 6.827 0.234 ;
     RECT  6.943 1.152 7.051 1.17 ;
     RECT  7.159 17.118 7.195 17.136 ;
     RECT  7.051 1.152 7.223 1.242 ;
     RECT  7.195 17.118 7.295 17.208 ;
     RECT  6.791 1.998 7.591 15.129 ;
     RECT  6.827 0.144 7.627 0.162 ;
     RECT  7.591 1.998 7.979 15.282 ;
     RECT  7.627 0.144 7.987 0.234 ;
     RECT  7.979 2.106 8.159 15.174 ;
     RECT  7.987 0.144 8.303 0.324 ;
     RECT  8.303 0.144 8.411 0.279 ;
     RECT  8.159 2.151 8.743 15.174 ;
     RECT  8.743 2.151 8.887 15.21 ;
     RECT  8.887 2.151 8.987 15.282 ;
     RECT  8.987 2.151 9.283 15.174 ;
     RECT  8.411 0.144 9.383 0.162 ;
     RECT  9.283 2.034 10.175 15.174 ;
     RECT  10.175 2.151 10.255 15.174 ;
     RECT  10.615 17.118 10.651 17.136 ;
     RECT  10.363 0.144 10.679 0.162 ;
     RECT  10.651 17.118 10.751 17.208 ;
     RECT  10.255 2.151 11.399 15.354 ;
     RECT  11.551 1.152 11.651 1.17 ;
     RECT  11.407 0.144 11.867 0.162 ;
     RECT  12.127 17.19 12.163 17.208 ;
     RECT  12.163 17.118 12.263 17.208 ;
     RECT  11.399 2.151 12.775 15.129 ;
     RECT  12.775 2.151 13.243 15.174 ;
     RECT  13.315 0.144 13.351 0.162 ;
     RECT  13.243 2.151 13.415 15.21 ;
     RECT  13.415 2.151 13.595 15.174 ;
     RECT  13.351 0.144 13.631 0.279 ;
     RECT  13.631 0.144 13.667 0.162 ;
     RECT  13.595 2.151 14.107 15.129 ;
     RECT  14.107 1.998 14.827 15.129 ;
     RECT  14.251 1.152 15.179 1.17 ;
     RECT  14.827 1.998 15.655 15.174 ;
     RECT  15.007 0.144 15.971 0.162 ;
     RECT  15.655 1.998 16.123 15.318 ;
     RECT  16.123 1.296 16.411 15.318 ;
     RECT  16.411 1.152 16.519 15.318 ;
     RECT  16.519 1.152 16.619 15.354 ;
     RECT  16.619 1.152 16.835 15.318 ;
     RECT  16.835 1.224 17.347 15.318 ;
     RECT  17.347 1.224 17.483 15.399 ;
     RECT  16.951 0.144 17.519 0.162 ;
     RECT  17.483 1.224 17.599 15.318 ;
     RECT  17.599 1.116 17.699 15.318 ;
     RECT  17.699 1.998 17.807 15.318 ;
     RECT  17.699 1.152 18.419 1.17 ;
     RECT  17.807 1.998 18.535 15.174 ;
     RECT  18.499 0.144 19.003 0.162 ;
     RECT  19.003 0.144 19.103 0.198 ;
     RECT  19.471 17.19 19.507 17.208 ;
     RECT  19.507 17.118 19.607 17.208 ;
     RECT  19.399 1.152 19.751 1.17 ;
     RECT  18.535 1.998 20.111 15.246 ;
     RECT  19.103 0.144 20.255 0.162 ;
     RECT  20.111 2.151 20.335 15.246 ;
     RECT  20.263 16.074 20.335 16.092 ;
     RECT  20.335 2.151 20.399 16.092 ;
     RECT  20.399 2.151 20.471 15.516 ;
     RECT  20.515 1.152 20.803 1.17 ;
     RECT  20.471 2.151 21.055 15.399 ;
     RECT  21.055 2.106 21.199 15.399 ;
     RECT  21.163 17.19 21.199 17.208 ;
     RECT  20.803 1.152 21.479 1.242 ;
     RECT  21.199 2.034 21.523 15.399 ;
     RECT  21.523 2.034 21.551 16.092 ;
     RECT  21.551 2.106 21.659 16.092 ;
     RECT  21.199 17.118 21.947 17.208 ;
     RECT  21.739 0.144 21.955 0.162 ;
     RECT  21.955 0.144 22.387 0.198 ;
     RECT  21.659 2.106 22.487 15.399 ;
     RECT  22.387 0.144 22.703 0.324 ;
     RECT  22.487 2.151 22.927 15.399 ;
     RECT  22.703 0.144 22.991 0.162 ;
     RECT  22.927 2.151 23.027 15.516 ;
     RECT  23.035 17.19 23.071 17.208 ;
     RECT  23.071 17.118 23.171 17.208 ;
     RECT  23.027 2.151 23.423 15.399 ;
     RECT  23.423 2.151 23.76 15.129 ;
     RECT  23.76 7.398 23.783 12.159 ;
     RECT  23.783 7.398 23.963 7.416 ;
     RECT  23.783 8.478 23.999 12.159 ;
     RECT  23.999 9.9 24.071 12.159 ;
     RECT  23.76 2.304 24.143 6.444 ;
     RECT  24.071 10.296 24.215 12.159 ;
     RECT  23.999 8.478 24.287 9.144 ;
     RECT  24.143 2.304 24.323 5.634 ;
     RECT  24.215 10.296 24.323 12.006 ;
     RECT  24.323 2.304 24.359 5.562 ;
     RECT  24.323 10.566 24.359 12.006 ;
     RECT  24.359 10.566 24.539 10.854 ;
     RECT  24.359 2.304 24.575 5.022 ;
     RECT  24.287 8.478 24.575 8.532 ;
     RECT  24.575 2.304 24.611 4.374 ;
     RECT  24.575 8.514 24.611 8.532 ;
     RECT  24.611 2.304 24.647 4.014 ;
     RECT  24.539 10.836 24.647 10.854 ;
     RECT  24.647 2.304 25.151 3.636 ;
     RECT  24.143 6.426 25.187 6.444 ;
     RECT  23.76 13.14 25.187 14.742 ;
     RECT  25.187 13.878 25.259 14.742 ;
     RECT  24.359 11.718 25.295 12.006 ;
     RECT  25.151 2.304 25.331 3.474 ;
     RECT  25.295 11.988 25.331 12.006 ;
     RECT  25.331 2.304 25.367 3.06 ;
     RECT  25.367 2.538 25.403 3.06 ;
     RECT  25.259 13.878 25.403 14.508 ;
     RECT  25.403 2.538 25.439 2.556 ;
     RECT  25.403 13.878 25.439 13.896 ;
    LAYER M3 ;
     RECT  2.052 0.031 2.07 0.108 ;
     RECT  5.292 0.031 5.31 0.108 ;
     RECT  2.052 0.108 23.634 0.187 ;
     RECT  2.052 0.187 23.67 1.387 ;
     RECT  1.98 1.387 23.67 2.065 ;
     RECT  1.44 2.065 23.67 2.101 ;
     RECT  24.516 0.139 24.534 2.371 ;
     RECT  25.344 2.299 25.362 2.371 ;
     RECT  24.516 2.371 25.362 2.533 ;
     RECT  1.116 2.101 23.67 3.643 ;
     RECT  1.008 3.643 23.67 3.883 ;
     RECT  0.972 3.883 23.67 4.123 ;
     RECT  0.972 4.123 23.742 4.171 ;
     RECT  24.516 2.533 25.434 4.171 ;
     RECT  0.972 4.171 25.434 4.459 ;
     RECT  0.936 4.459 25.434 12.164 ;
     RECT  0.936 12.164 23.922 12.893 ;
     RECT  2.196 12.893 23.922 12.989 ;
     RECT  2.196 12.989 23.778 13.199 ;
     RECT  0.936 12.893 1.062 13.739 ;
     RECT  24.66 12.164 25.434 13.739 ;
     RECT  25.2 13.739 25.434 13.901 ;
     RECT  1.044 13.739 1.062 14.009 ;
     RECT  25.2 13.901 25.398 14.009 ;
     RECT  25.236 14.009 25.398 14.513 ;
     RECT  25.236 14.513 25.254 14.747 ;
     RECT  2.196 13.199 23.742 17.148 ;
     RECT  4.176 17.148 4.302 17.213 ;
     RECT  7.2 17.148 7.29 17.213 ;
     RECT  10.656 17.148 10.746 17.213 ;
     RECT  12.132 17.148 12.258 17.213 ;
     RECT  19.476 17.148 19.602 17.213 ;
     RECT  21.168 17.148 21.942 17.213 ;
     RECT  23.04 17.148 23.166 17.213 ;
    LAYER M4 ;
     RECT  0.277 1.824 0.325 1.848 ;
     RECT  0.325 13.392 0.373 13.416 ;
     RECT  0.373 3.12 0.421 3.144 ;
     RECT  0.325 1.824 0.517 1.944 ;
     RECT  0.421 3.12 0.517 3.96 ;
     RECT  0.421 14.736 0.517 14.76 ;
     RECT  0.469 8.784 0.757 8.808 ;
     RECT  0.757 8.736 0.805 8.808 ;
     RECT  0.373 13.296 0.901 13.416 ;
     RECT  0.517 1.824 0.925 3.96 ;
     RECT  0.901 12.48 0.949 13.416 ;
     RECT  0.925 1.824 0.997 4.488 ;
     RECT  0.949 12.048 0.997 13.416 ;
     RECT  0.517 14.64 0.997 14.76 ;
     RECT  0.997 1.824 1.285 4.536 ;
     RECT  0.277 7.68 1.333 7.704 ;
     RECT  0.805 8.736 1.333 9.096 ;
     RECT  0.997 12.048 1.381 14.76 ;
     RECT  1.381 12.048 1.429 14.856 ;
     RECT  1.285 1.824 1.969 5.208 ;
     RECT  1.969 1.392 2.005 5.208 ;
     RECT  2.005 1.392 2.101 5.88 ;
     RECT  2.101 1.392 2.149 6.312 ;
     RECT  1.333 7.68 2.149 9.096 ;
     RECT  1.429 12.048 2.197 15.048 ;
     RECT  2.053 0.192 2.291 0.216 ;
     RECT  2.197 12 2.293 15.048 ;
     RECT  2.149 1.392 2.408 9.096 ;
     RECT  1.621 10.608 2.408 10.632 ;
     RECT  2.293 11.664 2.408 15.288 ;
     RECT  2.408 1.392 2.837 15.288 ;
     RECT  2.293 0.288 2.869 0.312 ;
     RECT  2.837 1.392 2.869 10.872 ;
     RECT  2.837 11.904 2.869 15.288 ;
     RECT  2.869 11.904 3.493 15.432 ;
     RECT  2.869 0.288 3.593 10.872 ;
     RECT  3.493 11.904 3.637 16.008 ;
     RECT  3.637 11.904 3.773 16.584 ;
     RECT  3.593 10.608 3.829 10.872 ;
     RECT  3.773 11.904 3.829 15.096 ;
     RECT  3.593 0.288 3.845 9.144 ;
     RECT  3.773 16.56 3.953 16.584 ;
     RECT  3.845 0.288 4.117 9.096 ;
     RECT  4.117 0.192 4.259 9.096 ;
     RECT  3.829 10.608 4.981 15.096 ;
     RECT  4.259 0.288 4.993 9.096 ;
     RECT  4.993 0.288 5.108 9.384 ;
     RECT  4.981 10.608 5.108 15.288 ;
     RECT  5.108 0.288 5.365 15.288 ;
     RECT  5.365 0.288 5.404 15.432 ;
     RECT  5.404 10.608 6.221 15.432 ;
     RECT  5.845 16.56 6.257 16.584 ;
     RECT  6.221 11.904 6.613 15.432 ;
     RECT  6.613 11.904 6.995 16.008 ;
     RECT  6.221 10.608 7.237 10.92 ;
     RECT  6.995 11.904 7.237 15.336 ;
     RECT  5.404 0.288 7.381 9.384 ;
     RECT  7.237 10.608 7.381 15.336 ;
     RECT  7.381 0.288 7.733 15.336 ;
     RECT  7.733 0.288 7.907 15.288 ;
     RECT  7.907 0.288 8.053 15.24 ;
     RECT  8.053 0.192 8.104 15.24 ;
     RECT  8.104 0.192 8.593 12.792 ;
     RECT  8.593 0.144 8.957 12.792 ;
     RECT  8.957 0.144 9.065 12.552 ;
     RECT  8.821 16.56 9.137 16.584 ;
     RECT  8.104 13.824 9.445 15.24 ;
     RECT  9.445 13.824 10.037 16.008 ;
     RECT  9.065 0.144 10.508 9.144 ;
     RECT  9.065 10.608 10.508 12.552 ;
     RECT  10.037 13.824 10.508 15.48 ;
     RECT  10.508 0.144 10.804 15.48 ;
     RECT  10.804 13.584 11.068 15.48 ;
     RECT  10.804 0.144 11.123 12.504 ;
     RECT  11.123 0.144 11.477 0.408 ;
     RECT  11.123 1.68 11.657 12.504 ;
     RECT  11.068 13.584 11.657 14.904 ;
     RECT  11.657 12.336 11.729 12.504 ;
     RECT  11.477 0.288 11.987 0.408 ;
     RECT  11.729 12.336 12.053 12.36 ;
     RECT  11.657 1.68 12.089 10.92 ;
     RECT  11.605 15.984 12.229 16.008 ;
     RECT  9.541 16.992 12.229 17.016 ;
     RECT  12.229 15.984 12.413 17.016 ;
     RECT  12.413 15.984 12.449 16.008 ;
     RECT  12.413 16.992 12.989 17.016 ;
     RECT  11.657 14.112 12.997 14.904 ;
     RECT  11.987 0.288 13.093 0.312 ;
     RECT  12.089 1.968 13.129 10.92 ;
     RECT  12.997 14.112 13.148 14.952 ;
     RECT  13.129 1.968 13.208 11.016 ;
     RECT  13.129 12.864 13.208 12.888 ;
     RECT  13.148 14.112 13.208 15.432 ;
     RECT  13.208 1.968 13.504 15.432 ;
     RECT  13.093 0.288 13.517 0.408 ;
     RECT  13.517 0.24 13.601 0.408 ;
     RECT  13.601 0.288 13.667 0.408 ;
     RECT  13.504 12.528 13.667 15.432 ;
     RECT  13.504 1.968 13.717 11.304 ;
     RECT  13.717 1.68 14.033 11.304 ;
     RECT  13.667 12.528 14.291 13.08 ;
     RECT  14.033 2.736 14.581 11.304 ;
     RECT  13.667 0.384 14.684 0.408 ;
     RECT  14.684 0.288 14.819 0.408 ;
     RECT  14.033 1.68 14.963 1.704 ;
     RECT  14.581 2.736 14.965 11.4 ;
     RECT  13.667 14.208 15.073 15.432 ;
     RECT  15.073 13.92 15.113 15.432 ;
     RECT  14.965 2.736 15.205 11.544 ;
     RECT  15.205 2.148 15.649 11.544 ;
     RECT  14.291 12.528 15.649 12.888 ;
     RECT  15.649 2.148 15.908 12.888 ;
     RECT  15.113 13.92 15.908 15.336 ;
     RECT  15.908 2.148 16.117 15.336 ;
     RECT  14.819 0.288 16.165 0.312 ;
     RECT  16.117 2.148 16.261 15.432 ;
     RECT  16.261 1.728 16.309 15.432 ;
     RECT  16.309 1.728 16.405 15.528 ;
     RECT  15.493 16.56 16.405 16.584 ;
     RECT  16.165 0.288 16.789 0.36 ;
     RECT  16.789 0.192 16.837 0.36 ;
     RECT  16.405 1.728 16.837 16.584 ;
     RECT  16.837 0.192 16.931 16.584 ;
     RECT  16.931 0.288 17.036 16.584 ;
     RECT  17.036 0.288 17.057 17.064 ;
     RECT  17.057 1.728 17.093 17.064 ;
     RECT  17.093 16.56 17.123 17.064 ;
     RECT  17.093 1.728 17.411 15.528 ;
     RECT  17.057 0.288 17.507 0.552 ;
     RECT  17.507 0.288 18.229 0.312 ;
     RECT  17.123 16.56 18.371 16.632 ;
     RECT  18.229 0.192 18.469 0.312 ;
     RECT  18.469 0.192 19.189 0.408 ;
     RECT  17.411 1.728 19.189 15.48 ;
     RECT  19.189 0.192 19.289 15.48 ;
     RECT  19.289 1.728 19.429 15.48 ;
     RECT  18.371 16.56 19.429 16.584 ;
     RECT  19.289 0.192 19.82 0.36 ;
     RECT  19.82 0.144 19.907 0.36 ;
     RECT  19.429 1.728 20.189 16.584 ;
     RECT  19.907 0.192 20.869 0.36 ;
     RECT  20.189 1.728 20.869 16.008 ;
     RECT  20.869 0.192 21.011 16.008 ;
     RECT  21.011 0.192 21.395 0.552 ;
     RECT  21.395 0.192 22.213 0.456 ;
     RECT  22.213 0.144 22.357 0.456 ;
     RECT  22.357 0.144 22.499 0.696 ;
     RECT  21.011 1.776 22.633 16.008 ;
     RECT  22.633 1.776 22.745 16.584 ;
     RECT  22.499 0.144 22.781 0.6 ;
     RECT  22.745 2.016 23.219 16.584 ;
     RECT  23.219 16.56 23.363 16.584 ;
     RECT  23.219 2.016 23.501 15.336 ;
     RECT  22.781 0.144 23.645 0.552 ;
     RECT  23.501 10.224 23.651 15.336 ;
     RECT  23.501 2.016 23.747 8.952 ;
     RECT  23.651 10.224 23.753 14.952 ;
     RECT  23.645 0.144 23.795 0.456 ;
     RECT  23.747 7.632 23.795 8.952 ;
     RECT  23.753 10.464 23.987 14.952 ;
     RECT  23.747 2.016 24.257 6.648 ;
     RECT  23.795 7.68 24.257 8.952 ;
     RECT  24.257 7.68 24.371 8.232 ;
     RECT  23.795 0.144 24.545 0.36 ;
     RECT  24.257 2.016 24.563 4.248 ;
     RECT  24.563 2.016 24.659 2.088 ;
     RECT  24.257 5.376 24.689 6.648 ;
     RECT  24.545 0.24 24.707 0.36 ;
     RECT  23.987 10.464 24.725 14.712 ;
     RECT  24.563 3.216 24.755 4.248 ;
     RECT  24.725 11.904 24.755 14.712 ;
     RECT  24.689 5.376 24.761 5.832 ;
     RECT  24.761 5.376 24.803 5.688 ;
     RECT  24.755 11.904 24.803 14.136 ;
     RECT  24.707 0.336 24.851 0.36 ;
     RECT  24.659 2.016 24.899 2.04 ;
     RECT  24.803 14.112 24.899 14.136 ;
     RECT  24.803 11.904 25.121 12.792 ;
     RECT  24.725 10.464 25.157 10.488 ;
     RECT  24.755 3.84 25.229 4.248 ;
     RECT  25.229 4.224 25.265 4.248 ;
     RECT  24.803 5.424 25.74 5.688 ;
     RECT  25.121 11.904 25.74 11.928 ;
     RECT  25.74 5.664 25.763 5.688 ;
     RECT  24.371 8.208 25.763 8.232 ;
    LAYER M5 ;
     RECT  19.872 0.133 19.896 0.144 ;
     RECT  22.224 0.133 22.248 0.144 ;
     RECT  2.256 0.144 23.736 0.181 ;
     RECT  2.064 0.181 23.736 0.229 ;
     RECT  2.064 0.229 24.696 0.325 ;
     RECT  0.288 1.813 0.312 1.861 ;
     RECT  2.064 0.325 24.84 2.005 ;
     RECT  0.288 1.861 0.84 2.053 ;
     RECT  0.288 2.053 0.888 2.533 ;
     RECT  2.064 2.005 24.888 2.533 ;
     RECT  0.288 2.533 24.888 5.413 ;
     RECT  0.288 5.413 25.656 5.653 ;
     RECT  0.288 5.653 25.752 7.715 ;
     RECT  0.336 7.715 25.752 8.243 ;
     RECT  0.336 8.243 24.888 8.675 ;
     RECT  0.336 8.675 11.976 9.059 ;
     RECT  12.96 8.675 24.888 9.347 ;
     RECT  6.432 9.059 11.976 9.395 ;
     RECT  12.96 9.347 14.76 9.395 ;
     RECT  14.736 9.395 14.76 9.731 ;
     RECT  6.432 9.395 11.832 9.827 ;
     RECT  12.96 9.395 13.512 10.307 ;
     RECT  7.8 9.827 11.832 10.355 ;
     RECT  7.8 10.355 11.496 10.883 ;
     RECT  13.056 10.307 13.512 10.883 ;
     RECT  0.336 9.059 5.412 11.365 ;
     RECT  6.432 9.827 6.504 11.365 ;
     RECT  7.8 10.883 9.384 11.365 ;
     RECT  15.9 9.347 24.888 11.365 ;
     RECT  10.5 10.883 11.496 12.035 ;
     RECT  14.592 11.365 24.888 12.035 ;
     RECT  0.336 11.365 9.384 12.517 ;
     RECT  10.5 12.035 11.448 12.517 ;
     RECT  17.808 12.035 24.888 12.611 ;
     RECT  14.592 12.035 16.392 12.755 ;
     RECT  13.2 10.883 13.512 13.045 ;
     RECT  14.592 12.755 16.344 13.045 ;
     RECT  0.336 12.517 11.448 13.427 ;
     RECT  0.432 13.427 11.448 13.573 ;
     RECT  18.6 12.611 24.888 13.715 ;
     RECT  20.688 13.715 24.888 14.147 ;
     RECT  0.432 13.573 11.496 14.245 ;
     RECT  13.2 13.045 16.344 14.245 ;
     RECT  20.688 14.147 24.744 14.723 ;
     RECT  0.432 14.245 16.392 14.771 ;
     RECT  1.392 14.771 16.392 14.821 ;
     RECT  18.6 13.715 19.416 14.821 ;
     RECT  20.688 14.723 23.976 14.821 ;
     RECT  1.392 14.821 17.592 14.867 ;
     RECT  18.6 14.821 23.976 14.963 ;
     RECT  1.44 14.867 17.592 15.059 ;
     RECT  2.256 15.059 17.592 15.349 ;
     RECT  18.6 14.963 23.64 15.349 ;
     RECT  2.256 15.349 23.64 17.104 ;
  END
END dsfd_dvrlyh_276_SN
END LIBRARY
